(* Logix 5000 project; controller SV160E2_EDS_AOI_CompactLogix_RSLogix_V28 vendor 1 type 14 code 108 rev 28.11; software revision 28.00; part 2 of 4 *)

ADD_ON_INSTRUCTION AMCI_SV160E2_Home_CCW   (* revision 1.0, vendor AMCI, ExecuteEnableInFalse *)
// Revision note:
// 8/2019 Version 0 Initial release of SV160E2 Add On Instructions.
// 3/17/20 Version 1 replaced the generic EDS file with a more complete V1.6 EDS file.
VAR_INPUT
   Status_Word_0 : INT; {required}
        .11   // Set when there is an input error
        .12   // set when there is a command error
        .13   // set when there is a configuration error
        .0   // Set when the SV160E2 is moving CW
        .1   // Set when SV160E2 is moving CCW
        .7   // SV160E2 Move Complete bit
   Status_Word_1 : INT; {required}
        .15   // Set when SV160E2 is enabled
   Programmed_Speed : DINT; {required}
   Acceleration : INT; {required}
   Deceleration : INT; {required}
   Maximum_Move_Torque : INT;
END_VAR
VAR_IN_OUT
   AMCI_SV160E2_output_data : _000A:SV160E2_9125ACD4:O:0; {required}
END_VAR
VAR_OUTPUT
   EN : BOOL; {access Read Only, visible}   // AOI EN bit
   ER : BOOL; {access Read Only, visible}   // AOI ER bit
END_VAR
VAR
   command_data_block : INT[10];
        [1]   // Command Word 1
        [3]   // Lower Target Position
        [5]   // Lower Programmed Speed
        [0]   // Command Word 0
        [2]   // Upper Target Position
        [4]   // Upper Programmed Speed
END_VAR

ROUTINE EnableInFalse   (* ladder *)
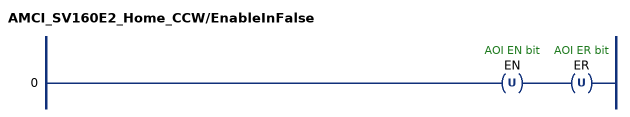
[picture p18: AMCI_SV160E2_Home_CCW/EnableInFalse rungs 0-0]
   0: OTU(EN)OTU(ER);
END_ROUTINE

ROUTINE Logic   (* ladder *)
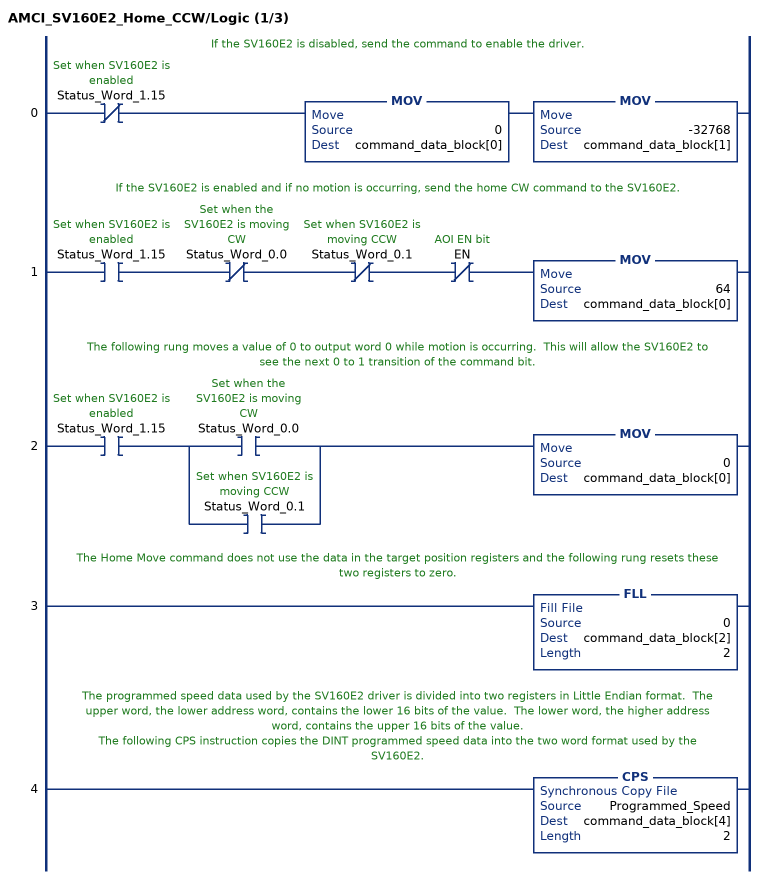
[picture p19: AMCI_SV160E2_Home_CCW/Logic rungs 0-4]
   // If the SV160E2 is disabled, send the command to enable the driver.
   0: XIO(Status_Word_1.15)MOV(0,command_data_block[0])MOV(-32768,command_data_block[1]);
   // If the SV160E2 is enabled and if no motion is occurring, send the home CW command to the SV160E2.
   1: XIC(Status_Word_1.15)XIO(Status_Word_0.0)XIO(Status_Word_0.1)XIO(EN)MOV(64,command_data_block[0]);
   // The following rung moves a value of 0 to output word 0 while motion is occurring.  This will allow the SV160E2 to see the next 0 to 1 transition of the command bit.
   2: XIC(Status_Word_1.15)[XIC(Status_Word_0.0) ,XIC(Status_Word_0.1) ]MOV(0,command_data_block[0]);
   // The Home Move command does not use the data in the target position registers and the following rung resets these two registers to zero.
   3: FLL(0,command_data_block[2],2);
   // The programmed speed data used by the SV160E2 driver is divided into two registers in Little Endian format.  The upper word, the lower address word, contains the lower 16 bits of the value.  The lower word, the higher address word, contains the upper 16 bits of the value.
   // The following CPS instruction copies the DINT programmed speed data into the two word format used by the SV160E2.
   4: CPS(Programmed_Speed,command_data_block[4],2);
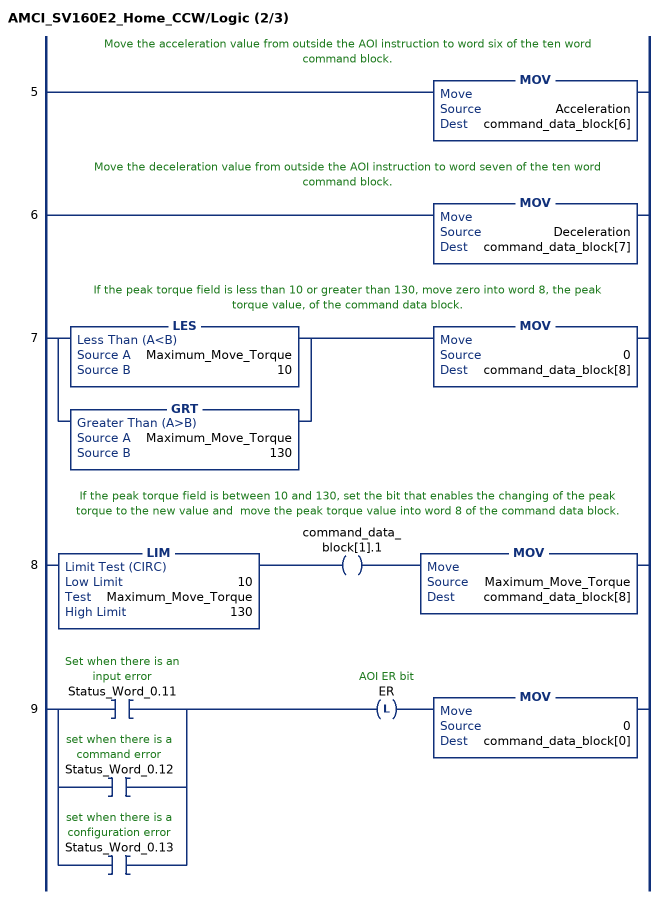
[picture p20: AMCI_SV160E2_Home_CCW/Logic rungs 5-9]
   // Move the acceleration value from outside the AOI instruction to word six of the ten word command block.
   5: MOV(Acceleration,command_data_block[6]);
   // Move the deceleration value from outside the AOI instruction to word seven of the ten word command block.
   6: MOV(Deceleration,command_data_block[7]);
   // If the peak torque field is less than 10 or greater than 130, move zero into word 8, the peak torque value, of the command data block.
   7: [LES(Maximum_Move_Torque,10) ,GRT(Maximum_Move_Torque,130) ]MOV(0,command_data_block[8]);
   // If the peak torque field is between 10 and 130, set the bit that enables the changing of the peak torque to the new value and  move the peak torque value into word 8 of the command data block.
   8: LIM(10,Maximum_Move_Torque,130)OTE(command_data_block[1].1)MOV(Maximum_Move_Torque,command_data_block[8]);
   9: [XIC(Status_Word_0.11) ,XIC(Status_Word_0.12) ,XIC(Status_Word_0.13) ]OTL(ER)MOV(0,command_data_block[0]);
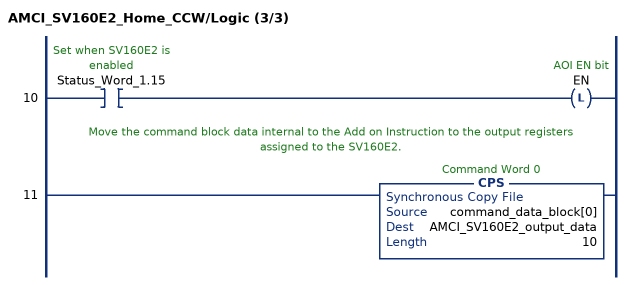
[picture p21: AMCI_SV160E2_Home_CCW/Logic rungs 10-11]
   10: XIC(Status_Word_1.15)OTL(EN);
   // Move the command block data internal to the Add on Instruction to the output registers assigned to the SV160E2.
   11: CPS(command_data_block[0],AMCI_SV160E2_output_data,10);
END_ROUTINE
END_ADD_ON_INSTRUCTION

ADD_ON_INSTRUCTION AMCI_SV160E2_Home_CW   (* revision 1.0, vendor AMCI, ExecuteEnableInFalse *)
// Revision note:
// 8/2019 Version 0 Initial release of SV160E2 Add On Instructions.
// 3/17/20 Version 1 replaced the generic EDS file with a more complete V1.6 EDS file.
VAR_INPUT
   Status_Word_0 : INT; {required}
        .11   // Set when there is an input error
        .12   // set when there is a command error
        .13   // set when there is a configuration error
        .0   // Set when the SV160E2 is moving CW
        .1   // Set when SV160E2 is moving CCW
        .7   // SV160E2 Move Complete bit
   Status_Word_1 : INT; {required}
        .15   // Set when SV160E2 is enabled
   Programmed_Speed : DINT; {required}
   Acceleration : INT; {required}
   Deceleration : INT; {required}
   Maximum_Move_Torque : INT;
END_VAR
VAR_IN_OUT
   AMCI_SV160E2_output_data : _000A:SV160E2_9125ACD4:O:0; {required}
END_VAR
VAR_OUTPUT
   EN : BOOL; {access Read Only, visible}   // AOI EN bit
   ER : BOOL; {access Read Only, visible}   // AOI ER bit
END_VAR
VAR
   command_data_block : INT[10];
        [1]   // Command Word 1
        [0]   // Command Word 0
        [3]   // Lower Target Position
        [5]   // Lower Programmed Speed
        [2]   // Upper Target Position
        [4]   // Upper Programmed Speed
END_VAR

ROUTINE EnableInFalse   (* ladder *)
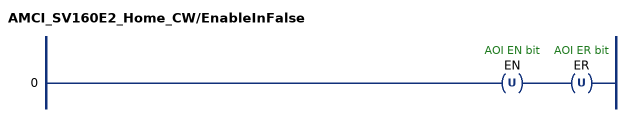
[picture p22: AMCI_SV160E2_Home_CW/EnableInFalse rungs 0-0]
   0: OTU(EN)OTU(ER);
END_ROUTINE

ROUTINE Logic   (* ladder *)
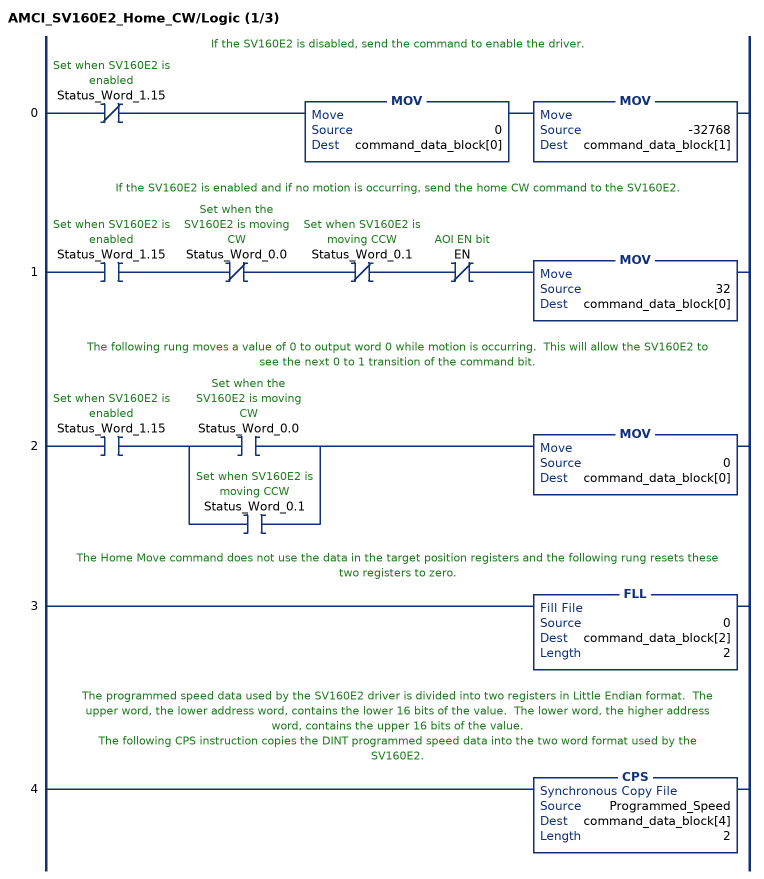
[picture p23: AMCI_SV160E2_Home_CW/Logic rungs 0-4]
   // If the SV160E2 is disabled, send the command to enable the driver.
   0: XIO(Status_Word_1.15)MOV(0,command_data_block[0])MOV(-32768,command_data_block[1]);
   // If the SV160E2 is enabled and if no motion is occurring, send the home CW command to the SV160E2.
   1: XIC(Status_Word_1.15)XIO(Status_Word_0.0)XIO(Status_Word_0.1)XIO(EN)MOV(32,command_data_block[0]);
   // The following rung moves a value of 0 to output word 0 while motion is occurring.  This will allow the SV160E2 to see the next 0 to 1 transition of the command bit.
   2: XIC(Status_Word_1.15)[XIC(Status_Word_0.0) ,XIC(Status_Word_0.1) ]MOV(0,command_data_block[0]);
   // The Home Move command does not use the data in the target position registers and the following rung resets these two registers to zero.
   3: FLL(0,command_data_block[2],2);
   // The programmed speed data used by the SV160E2 driver is divided into two registers in Little Endian format.  The upper word, the lower address word, contains the lower 16 bits of the value.  The lower word, the higher address word, contains the upper 16 bits of the value.
   // The following CPS instruction copies the DINT programmed speed data into the two word format used by the SV160E2.
   4: CPS(Programmed_Speed,command_data_block[4],2);
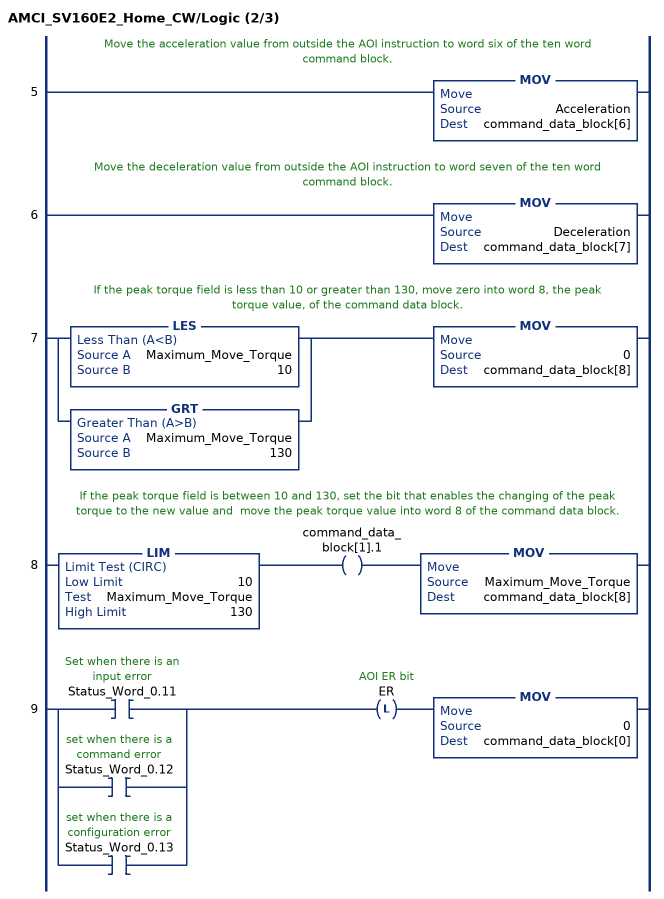
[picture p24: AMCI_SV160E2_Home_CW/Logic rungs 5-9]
   // Move the acceleration value from outside the AOI instruction to word six of the ten word command block.
   5: MOV(Acceleration,command_data_block[6]);
   // Move the deceleration value from outside the AOI instruction to word seven of the ten word command block.
   6: MOV(Deceleration,command_data_block[7]);
   // If the peak torque field is less than 10 or greater than 130, move zero into word 8, the peak torque value, of the command data block.
   7: [LES(Maximum_Move_Torque,10) ,GRT(Maximum_Move_Torque,130) ]MOV(0,command_data_block[8]);
   // If the peak torque field is between 10 and 130, set the bit that enables the changing of the peak torque to the new value and  move the peak torque value into word 8 of the command data block.
   8: LIM(10,Maximum_Move_Torque,130)OTE(command_data_block[1].1)MOV(Maximum_Move_Torque,command_data_block[8]);
   9: [XIC(Status_Word_0.11) ,XIC(Status_Word_0.12) ,XIC(Status_Word_0.13) ]OTL(ER)MOV(0,command_data_block[0]);
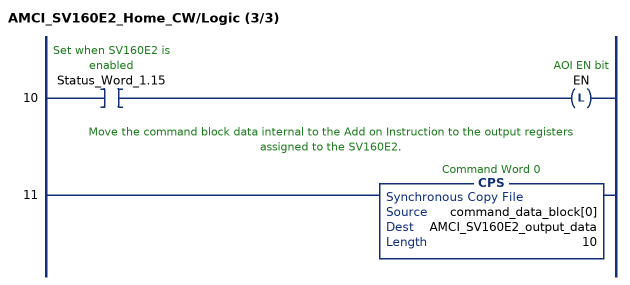
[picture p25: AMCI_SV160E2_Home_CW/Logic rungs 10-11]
   10: XIC(Status_Word_1.15)OTL(EN);
   // Move the command block data internal to the Add on Instruction to the output registers assigned to the SV160E2.
   11: CPS(command_data_block[0],AMCI_SV160E2_output_data,10);
END_ROUTINE
END_ADD_ON_INSTRUCTION

ADD_ON_INSTRUCTION AMCI_SV160E2_Immediate_Stop   (* revision 1.0, vendor AMCI *)
// Revision note:
// 8/2019 Version 0 Initial release of SV160E2 Add On Instructions.
// 3/17/20 Version 1 replaced the generic EDS file with a more complete V1.6 EDS file.
VAR_IN_OUT
   AMCI_SV160E2_OUTPUT_DATA : _000A:SV160E2_9125ACD4:O:0; {required}
END_VAR
VAR
   command_data_block : INT[10];
        [1]   // Command Bits LSW
        [0]   // Command Bits MSW
        [3]   // Lower Target Position
        [5]   // Lower Programmed Speed
        [2]   // Upper Target Position
        [4]   // Upper Programmed Speed
END_VAR

ROUTINE Logic   (* ladder *)
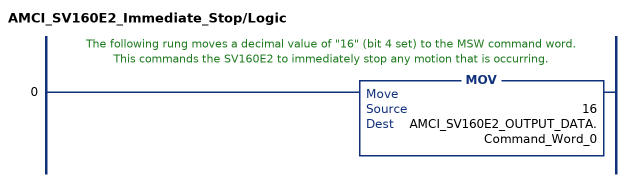
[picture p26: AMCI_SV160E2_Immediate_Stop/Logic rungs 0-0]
   // The following rung moves a decimal value of "16" (bit 4 set) to the MSW command word.  This commands the SV160E2 to immediately stop any motion that is occurring.
   0: MOV(16,AMCI_SV160E2_OUTPUT_DATA.Command_Word_0);
END_ROUTINE
END_ADD_ON_INSTRUCTION

ADD_ON_INSTRUCTION AMCI_SV160E2_Jog_CCW   (* revision 1.0, vendor AMCI, ExecuteEnableInFalse *)
// Revision note:
// 8/2019 Version 0 Initial release of SV160E2 Add On Instructions.
// 3/17/20 Version 1 replaced the generic EDS file with a more complete V1.6 EDS file.
VAR_INPUT
   Status_Word_0 : INT; {required}
        .11   // Set when there is an input error
        .12   // set when there is a command error
        .13   // set when there is a configuration error
        .0   // Set when the SV160E2 is moving CW
        .1   // Set when SV160E2 is moving CCW
        .3   // set when the SV160E2 is stopped
        .7   // SV160E2 Move Complete bit
   Status_Word_1 : INT; {required}
        .15   // Set when SV160E2 is enabled
   Programmed_Speed : DINT; {required}
   Acceleration : INT; {required}
   Deceleration : INT; {required}
   Maximum_Move_Torque : INT;
END_VAR
VAR_IN_OUT
   AMCI_SV160E2_output_data : _000A:SV160E2_9125ACD4:O:0; {required}
END_VAR
VAR_OUTPUT
   EN : BOOL; {access Read Only, visible}   // AOI EN bit
   jog_ccw_occurring : BOOL; {access Read Only, visible}
   ER : BOOL; {access Read Only, visible}   // AOI ER bit
END_VAR
VAR
   command_data_block : INT[10];
        [1]   // Command Word 1
        [3]   // Lower Target Position
        [5]   // Lower Programmed Speed
        [0]   // Command Word 0
        [2]   // Upper Target Position
        [4]   // Upper Programmed Speed
END_VAR

ROUTINE EnableInFalse   (* ladder *)
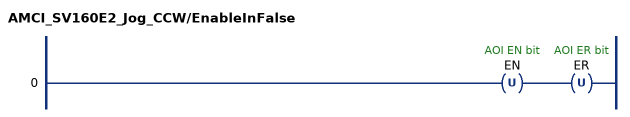
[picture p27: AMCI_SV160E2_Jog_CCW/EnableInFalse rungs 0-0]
   0: OTU(EN)OTU(ER);
END_ROUTINE

ROUTINE Logic   (* ladder *)
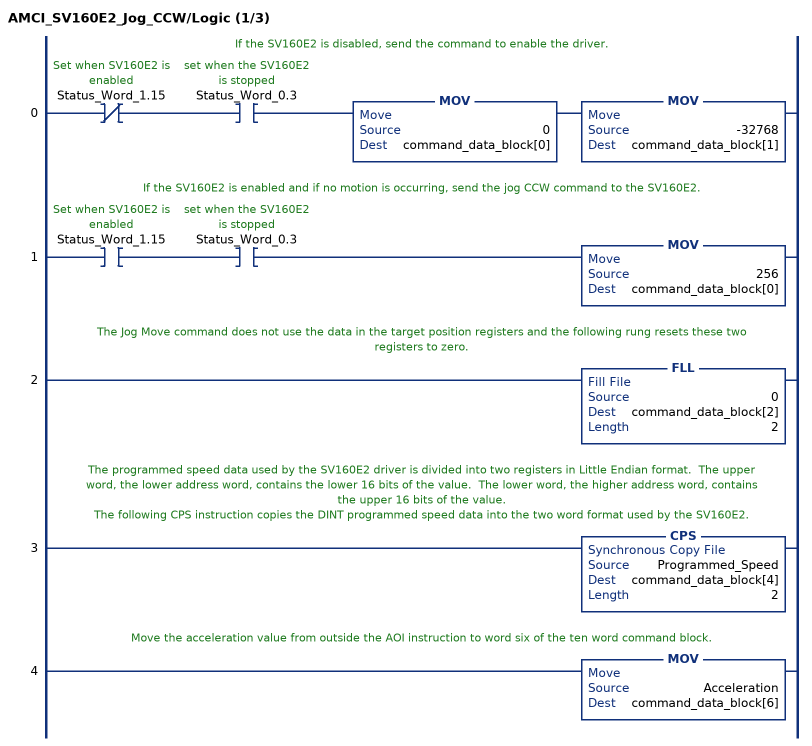
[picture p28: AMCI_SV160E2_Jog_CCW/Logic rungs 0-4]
   // If the SV160E2 is disabled, send the command to enable the driver.
   0: XIO(Status_Word_1.15)XIC(Status_Word_0.3)MOV(0,command_data_block[0])MOV(-32768,command_data_block[1]);
   // If the SV160E2 is enabled and if no motion is occurring, send the jog CCW command to the SV160E2.
   1: XIC(Status_Word_1.15)XIC(Status_Word_0.3)MOV(256,command_data_block[0]);
   // The Jog Move command does not use the data in the target position registers and the following rung resets these two registers to zero.
   2: FLL(0,command_data_block[2],2);
   // The programmed speed data used by the SV160E2 driver is divided into two registers in Little Endian format.  The upper word, the lower address word, contains the lower 16 bits of the value.  The lower word, the higher address word, contains the upper 16 bits of the value.
   // The following CPS instruction copies the DINT programmed speed data into the two word format used by the SV160E2.
   3: CPS(Programmed_Speed,command_data_block[4],2);
   // Move the acceleration value from outside the AOI instruction to word six of the ten word command block.
   4: MOV(Acceleration,command_data_block[6]);
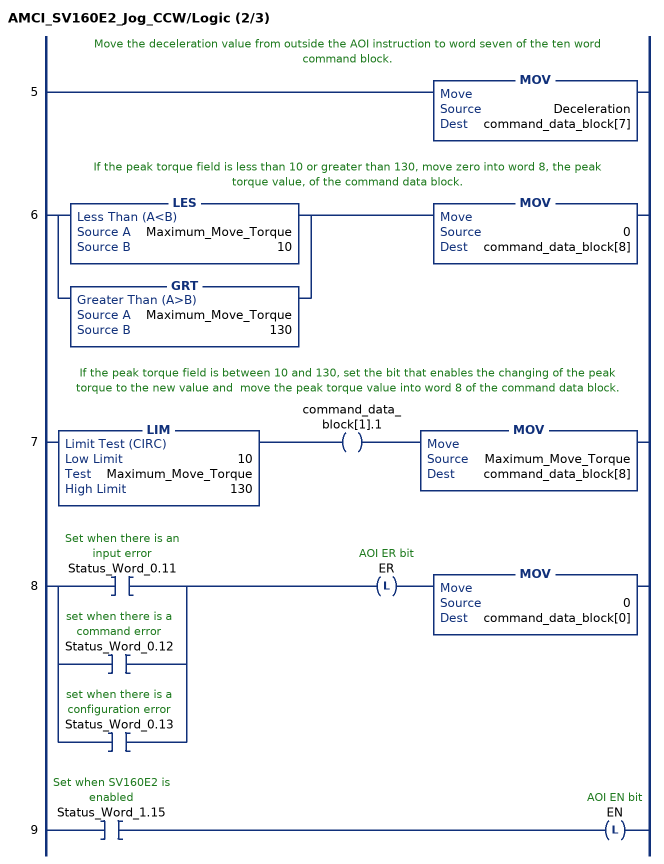
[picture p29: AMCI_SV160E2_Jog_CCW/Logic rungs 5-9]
   // Move the deceleration value from outside the AOI instruction to word seven of the ten word command block.
   5: MOV(Deceleration,command_data_block[7]);
   // If the peak torque field is less than 10 or greater than 130, move zero into word 8, the peak torque value, of the command data block.
   6: [LES(Maximum_Move_Torque,10) ,GRT(Maximum_Move_Torque,130) ]MOV(0,command_data_block[8]);
   // If the peak torque field is between 10 and 130, set the bit that enables the changing of the peak torque to the new value and  move the peak torque value into word 8 of the command data block.
   7: LIM(10,Maximum_Move_Torque,130)OTE(command_data_block[1].1)MOV(Maximum_Move_Torque,command_data_block[8]);
   8: [XIC(Status_Word_0.11) ,XIC(Status_Word_0.12) ,XIC(Status_Word_0.13) ]OTL(ER)MOV(0,command_data_block[0]);
   9: XIC(Status_Word_1.15)OTL(EN);
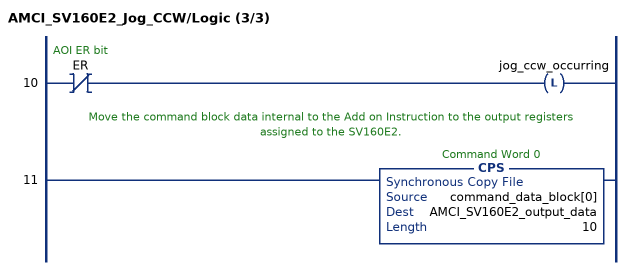
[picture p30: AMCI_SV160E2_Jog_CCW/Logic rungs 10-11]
   10: XIO(ER)OTL(jog_ccw_occurring);
   // Move the command block data internal to the Add on Instruction to the output registers assigned to the SV160E2.
   11: CPS(command_data_block[0],AMCI_SV160E2_output_data,10);
END_ROUTINE
END_ADD_ON_INSTRUCTION

ADD_ON_INSTRUCTION AMCI_SV160E2_Jog_CW   (* revision 1.0, vendor AMCI, ExecuteEnableInFalse *)
// Revision note:
// 8/2019 Version 0 Initial release of SV160E2 Add On Instructions.
// 3/17/20 Version 1 replaced the generic EDS file with a more complete V1.6 EDS file.
VAR_INPUT
   Status_Word_0 : INT; {required}
        .11   // Set when there is an input error
        .12   // set when there is a command error
        .13   // set when there is a configuration error
        .0   // Set when the SV160E2 is moving CW
        .1   // Set when SV160E2 is moving CCW
        .3   // set when the SV160E2 is stopped
        .7   // SV160E2 Move Complete bit
   Status_Word_1 : INT; {required}
        .15   // Set when SV160E2 is enabled
   Programmed_Speed : DINT; {required}
   Acceleration : INT; {required}
   Deceleration : INT; {required}
   Maximum_Move_Torque : INT;
END_VAR
VAR_IN_OUT
   AMCI_SV160E2_output_data : _000A:SV160E2_9125ACD4:O:0; {required}
END_VAR
VAR_OUTPUT
   EN : BOOL; {access Read Only, visible}   // AOI EN bit
   jog_cw_occurring : BOOL; {access Read Only, visible}
   ER : BOOL; {access Read Only, visible}   // AOI ER bit
END_VAR
VAR
   command_data_block : INT[10];
        [3]   // Lower Target Position
        [5]   // Lower Programmed Speed
        [2]   // Upper Target Position
        [4]   // Upper Programmed Speed
        [1]   // Command Word 1
        [0]   // Command Word 0
END_VAR

ROUTINE EnableInFalse   (* ladder *)
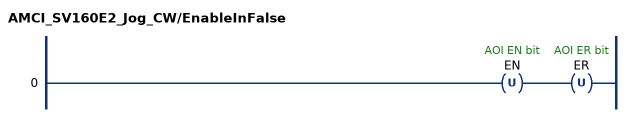
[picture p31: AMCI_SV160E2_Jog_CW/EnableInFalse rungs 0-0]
   0: OTU(EN)OTU(ER);
END_ROUTINE

ROUTINE Logic   (* ladder *)
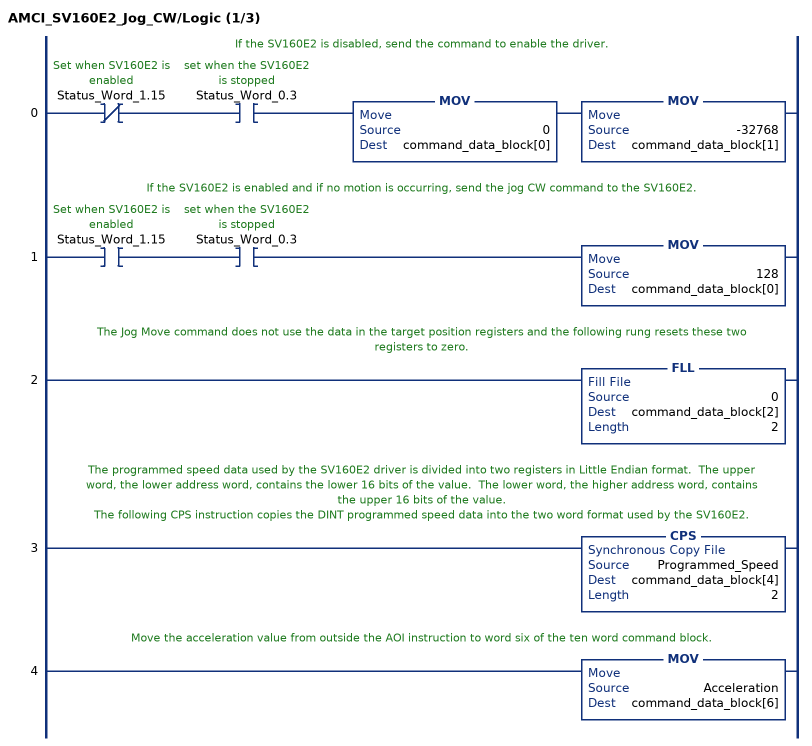
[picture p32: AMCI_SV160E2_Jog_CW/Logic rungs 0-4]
   // If the SV160E2 is disabled, send the command to enable the driver.
   0: XIO(Status_Word_1.15)XIC(Status_Word_0.3)MOV(0,command_data_block[0])MOV(-32768,command_data_block[1]);
   // If the SV160E2 is enabled and if no motion is occurring, send the jog CW command to the SV160E2.
   1: XIC(Status_Word_1.15)XIC(Status_Word_0.3)MOV(128,command_data_block[0]);
   // The Jog Move command does not use the data in the target position registers and the following rung resets these two registers to zero.
   2: FLL(0,command_data_block[2],2);
   // The programmed speed data used by the SV160E2 driver is divided into two registers in Little Endian format.  The upper word, the lower address word, contains the lower 16 bits of the value.  The lower word, the higher address word, contains the upper 16 bits of the value.
   // The following CPS instruction copies the DINT programmed speed data into the two word format used by the SV160E2.
   3: CPS(Programmed_Speed,command_data_block[4],2);
   // Move the acceleration value from outside the AOI instruction to word six of the ten word command block.
   4: MOV(Acceleration,command_data_block[6]);
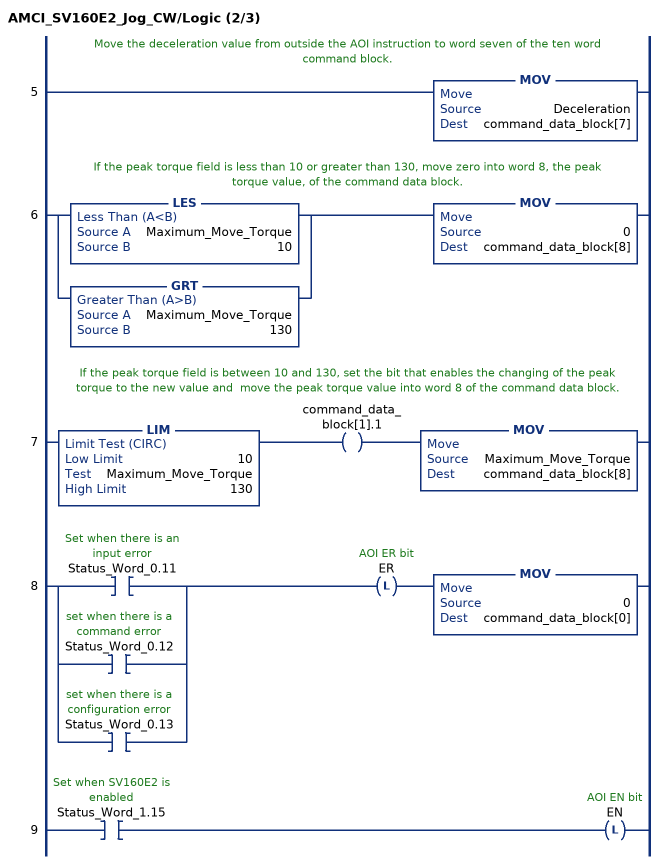
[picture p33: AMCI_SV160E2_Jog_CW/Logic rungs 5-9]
   // Move the deceleration value from outside the AOI instruction to word seven of the ten word command block.
   5: MOV(Deceleration,command_data_block[7]);
   // If the peak torque field is less than 10 or greater than 130, move zero into word 8, the peak torque value, of the command data block.
   6: [LES(Maximum_Move_Torque,10) ,GRT(Maximum_Move_Torque,130) ]MOV(0,command_data_block[8]);
   // If the peak torque field is between 10 and 130, set the bit that enables the changing of the peak torque to the new value and  move the peak torque value into word 8 of the command data block.
   7: LIM(10,Maximum_Move_Torque,130)OTE(command_data_block[1].1)MOV(Maximum_Move_Torque,command_data_block[8]);
   8: [XIC(Status_Word_0.11) ,XIC(Status_Word_0.12) ,XIC(Status_Word_0.13) ]OTL(ER)MOV(0,command_data_block[0]);
   9: XIC(Status_Word_1.15)OTL(EN);
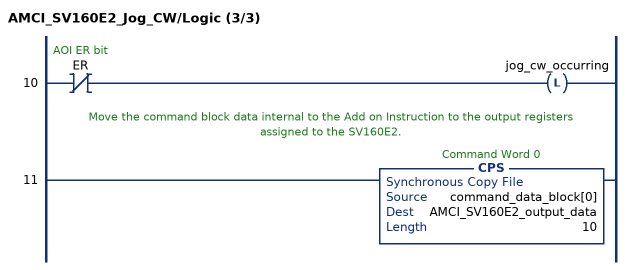
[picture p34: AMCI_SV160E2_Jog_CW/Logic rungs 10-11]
   10: XIO(ER)OTL(jog_cw_occurring);
   // Move the command block data internal to the Add on Instruction to the output registers assigned to the SV160E2.
   11: CPS(command_data_block[0],AMCI_SV160E2_output_data,10);
END_ROUTINE
END_ADD_ON_INSTRUCTION

ADD_ON_INSTRUCTION AMCI_SV160E2_Preset_on_Enable   (* revision 1.0, vendor AMCI, ExecuteEnableInFalse *)
// Revision note:
// 8/2019 Version 0 Initial release of SV160E2 Add On Instructions.
// 3/17/20 Version 1 replaced the generic EDS file with a more complete V1.6 EDS file.
VAR_IN_OUT
   AMCI_SV160E2_output_data : _000A:SV160E2_9125ACD4:O:0; {required}
END_VAR
VAR_OUTPUT
   EN : BOOL; {access Read Only, visible}
END_VAR
VAR
   command_data_block : INT[10];
        [1]   // Command Word 1
        [0]   // Command Word 0
        [3]   // Lower Target Position
        [5]   // Lower Programmed Speed
END_VAR

ROUTINE EnableInFalse   (* ladder *)
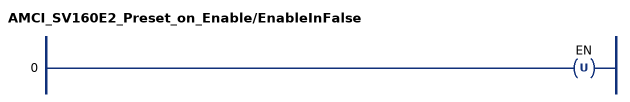
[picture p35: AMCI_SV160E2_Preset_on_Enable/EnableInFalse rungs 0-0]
   0: OTU(EN);
END_ROUTINE
(* Logix 5000 project; controller SV160E2_EDS_AOI_CompactLogix_RSLogix_V28 vendor 1 type 14 code 108 rev 28.11; software revision 28.00; part 3 of 4 *)
(* AMCI_SV160E2_Preset_on_Enable, continued *)

ROUTINE Logic   (* ladder *)
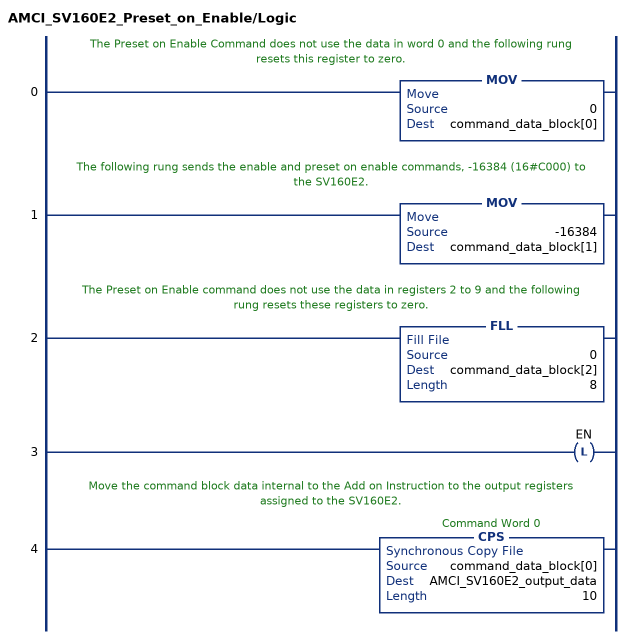
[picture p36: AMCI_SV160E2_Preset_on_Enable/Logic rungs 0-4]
   // The Preset on Enable Command does not use the data in word 0 and the following rung resets this register to zero.
   0: MOV(0,command_data_block[0]);
   // The following rung sends the enable and preset on enable commands, -16384 (16#C000) to the SV160E2.
   1: MOV(-16384,command_data_block[1]);
   // The Preset on Enable command does not use the data in registers 2 to 9 and the following rung resets these registers to zero.
   2: FLL(0,command_data_block[2],8);
   3: OTL(EN);
   // Move the command block data internal to the Add on Instruction to the output registers assigned to the SV160E2.
   4: CPS(command_data_block[0],AMCI_SV160E2_output_data,10);
END_ROUTINE
END_ADD_ON_INSTRUCTION

ADD_ON_INSTRUCTION AMCI_SV160E2_Preset_Position   (* revision 1.0, vendor AMCI, ExecuteEnableInFalse *)
// Revision note:
// 8/2019 Version 0 Initial release of SV160E2 Add On Instructions.
// 3/17/20 Version 1 replaced the generic EDS file with a more complete V1.6 EDS file.
VAR_INPUT
   Status_Word_0 : INT; {required}
        .11   // Set when there is an input error
        .12   // set when there is a command error
        .13   // set when there is a configuration error
        .0   // Set when the SV160E2 is moving CW
        .1   // Set when SV160E2 is moving CCW
        .7   // SV160E2 Move Complete bit
   Status_Word_1 : INT; {required}
        .15   // Set when SV160E2 is enabled
   save_in_flash_0_no_1_yes : BOOL; {required}
   Target_Position : DINT; {required}
END_VAR
VAR_IN_OUT
   AMCI_SV160E2_output_data : _000A:SV160E2_9125ACD4:O:0; {required}
END_VAR
VAR_OUTPUT
   EN : BOOL; {visible}
END_VAR
VAR
   command_data_block : INT[10];
        [5]   // Lower Programmed Speed
        [2]   // Upper Target Position
        [1]   // Command Word 1
        [0]   // Command Word 0
        [3]   // Lower Target Position
END_VAR

ROUTINE EnableInFalse   (* ladder *)
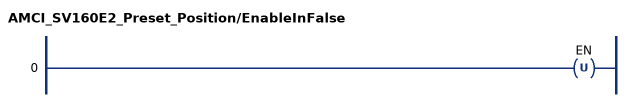
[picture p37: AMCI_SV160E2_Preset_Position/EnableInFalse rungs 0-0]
   0: OTU(EN);
END_ROUTINE

ROUTINE Logic   (* ladder *)
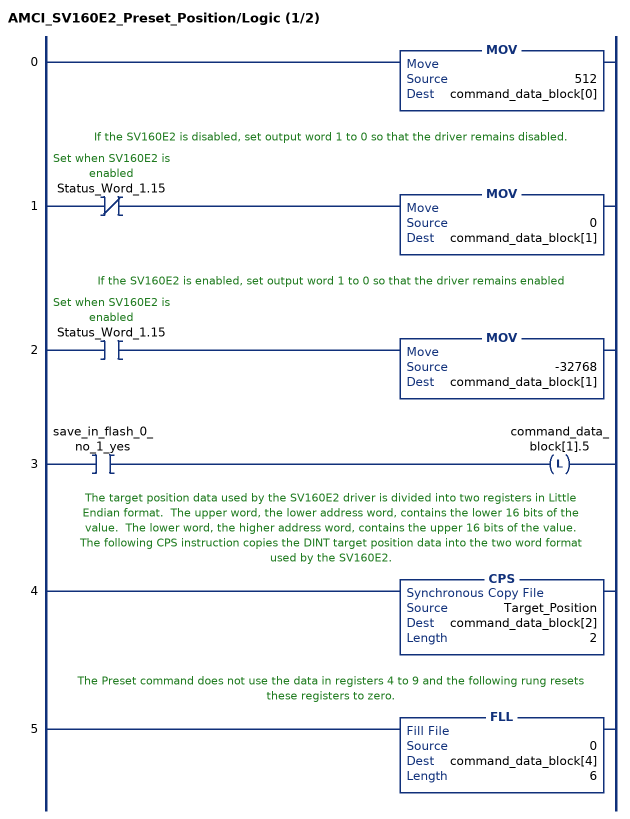
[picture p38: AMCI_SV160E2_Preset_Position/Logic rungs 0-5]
   0: MOV(512,command_data_block[0]);
   // If the SV160E2 is disabled, set output word 1 to 0 so that the driver remains disabled.
   1: XIO(Status_Word_1.15)MOV(0,command_data_block[1]);
   // If the SV160E2 is enabled, set output word 1 to 0 so that the driver remains enabled
   2: XIC(Status_Word_1.15)MOV(-32768,command_data_block[1]);
   3: XIC(save_in_flash_0_no_1_yes)OTL(command_data_block[1].5);
   // The target position data used by the SV160E2 driver is divided into two registers in Little Endian format.  The upper word, the lower address word, contains the lower 16 bits of the value.  The lower word, the higher address word, contains the upper 16 bits of the value.
   // The following CPS instruction copies the DINT target position data into the two word format used by the SV160E2.
   4: CPS(Target_Position,command_data_block[2],2);
   // The Preset command does not use the data in registers 4 to 9 and the following rung resets these registers to zero.
   5: FLL(0,command_data_block[4],6);
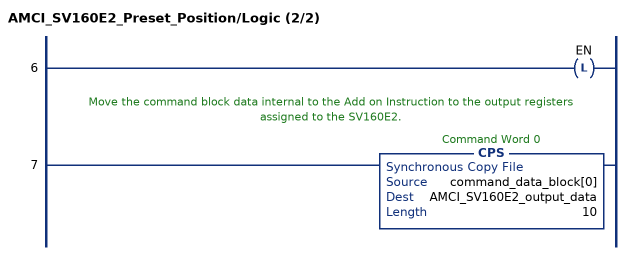
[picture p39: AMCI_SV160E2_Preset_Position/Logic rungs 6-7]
   6: OTL(EN);
   // Move the command block data internal to the Add on Instruction to the output registers assigned to the SV160E2.
   7: CPS(command_data_block[0],AMCI_SV160E2_output_data,10);
END_ROUTINE
END_ADD_ON_INSTRUCTION

ADD_ON_INSTRUCTION AMCI_SV160E2_Registration_Move_CCW   (* revision 1.0, vendor AMCI, ExecuteEnableInFalse *)
// Revision note:
// 8/2019 Version 0 Initial release of SV160E2 Add On Instructions.
// 3/17/20 Version 1 replaced the generic EDS file with a more complete V1.6 EDS file.
VAR_INPUT
   Status_Word_0 : INT; {required}
   Status_Word_1 : INT; {required}
   Type_0_for_standard_1_for_indexed : BOOL;
   Stopping_Distance : DINT; {required}
   Programmed_Speed : DINT; {required}
   Acceleration : INT; {required}
   Deceleration : INT; {required}
   Minimum_Registration_Move_Distance : DINT; {required}
END_VAR
VAR_IN_OUT
   AMCI_SV160E2_output_data : _000A:SV160E2_9125ACD4:O:0; {required}
END_VAR
VAR_OUTPUT
   EN : BOOL; {visible}
   Registration_Move_CW_Occurring : BOOL; {access Read Only, visible}
   ER : BOOL; {visible}
END_VAR
VAR
   Upper_Result_X_1000 : DINT;
   command_data_block : INT[10];
        [1]   // Command Bits LSW
        [0]   // Command Bits MSW
        [3]   // Lower Target Position
        [5]   // Lower Programmed Speed
        [2]   // Upper Target Position
        [4]   // Upper Programmed Speed
END_VAR

ROUTINE EnableInFalse   (* ladder *)
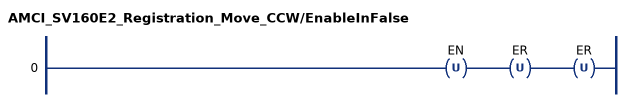
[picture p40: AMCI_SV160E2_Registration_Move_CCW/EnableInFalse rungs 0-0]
   0: OTU(EN)OTU(ER)OTU(ER);
END_ROUTINE

ROUTINE Logic   (* ladder *)
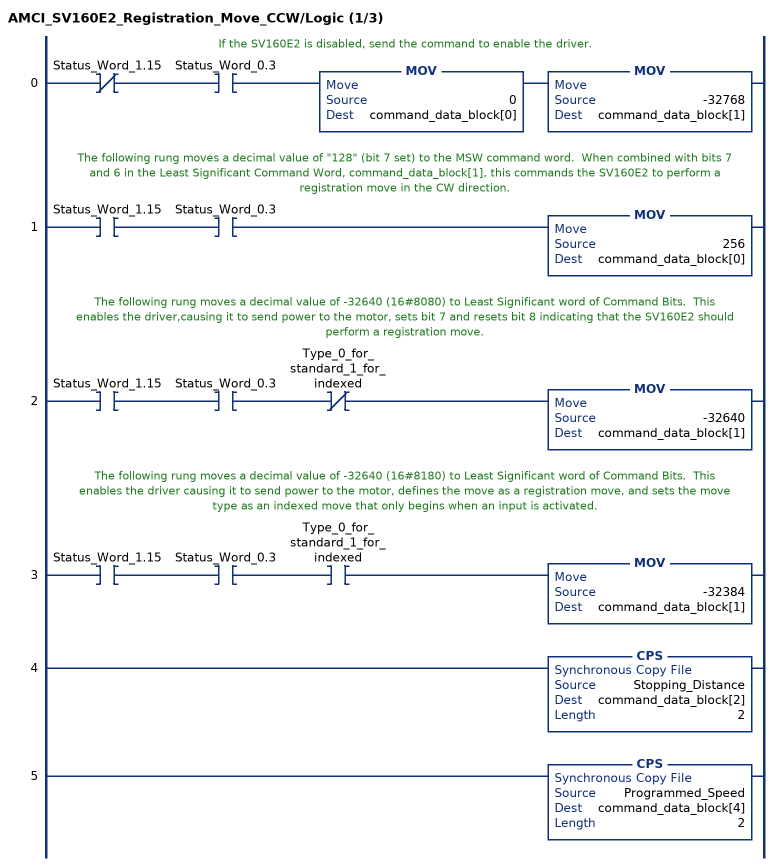
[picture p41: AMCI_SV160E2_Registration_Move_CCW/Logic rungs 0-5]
   // If the SV160E2 is disabled, send the command to enable the driver.
   0: XIO(Status_Word_1.15)XIC(Status_Word_0.3)MOV(0,command_data_block[0])MOV(-32768,command_data_block[1]);
   // The following rung moves a decimal value of "128" (bit 7 set) to the MSW command word.  When combined with bits 7 and 6 in the Least Significant Command Word, command_data_block[1], this commands the SV160E2 to perform a registration move in the CW direction.
   1: XIC(Status_Word_1.15)XIC(Status_Word_0.3)MOV(256,command_data_block[0]);
   // The following rung moves a decimal value of -32640 (16#8080) to Least Significant word of Command Bits.  This enables the driver,causing it to send power to the motor, sets bit 7 and resets bit 8 indicating that the SV160E2 should perform a registration move.
   2: XIC(Status_Word_1.15)XIC(Status_Word_0.3)XIO(Type_0_for_standard_1_for_indexed)MOV(-32640,command_data_block[1]);
   // The following rung moves a decimal value of -32640 (16#8180) to Least Significant word of Command Bits.  This enables the driver causing it to send power to the motor, defines the move as a registration move, and sets the move type as an indexed move that only begins when an input is activated.
   3: XIC(Status_Word_1.15)XIC(Status_Word_0.3)XIC(Type_0_for_standard_1_for_indexed)MOV(-32384,command_data_block[1]);
   4: CPS(Stopping_Distance,command_data_block[2],2);
   5: CPS(Programmed_Speed,command_data_block[4],2);
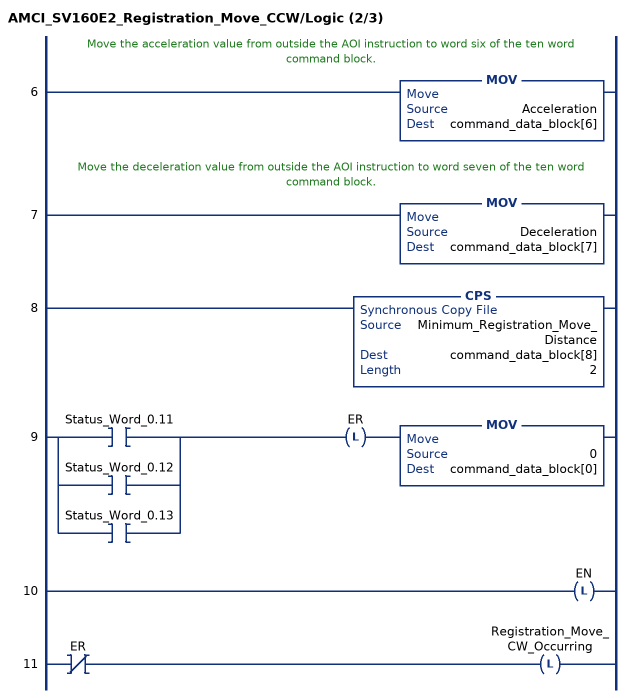
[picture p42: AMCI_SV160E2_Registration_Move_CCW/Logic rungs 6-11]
   // Move the acceleration value from outside the AOI instruction to word six of the ten word command block.
   6: MOV(Acceleration,command_data_block[6]);
   // Move the deceleration value from outside the AOI instruction to word seven of the ten word command block.
   7: MOV(Deceleration,command_data_block[7]);
   8: CPS(Minimum_Registration_Move_Distance,command_data_block[8],2);
   9: [XIC(Status_Word_0.11) ,XIC(Status_Word_0.12) ,XIC(Status_Word_0.13) ]OTL(ER)MOV(0,command_data_block[0]);
   10: OTL(EN);
   11: XIO(ER)OTL(Registration_Move_CW_Occurring);
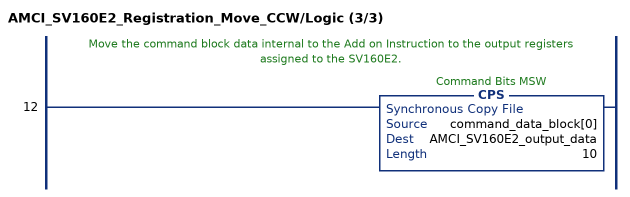
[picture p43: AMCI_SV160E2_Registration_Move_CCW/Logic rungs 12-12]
   // Move the command block data internal to the Add on Instruction to the output registers assigned to the SV160E2.
   12: CPS(command_data_block[0],AMCI_SV160E2_output_data,10);
END_ROUTINE
END_ADD_ON_INSTRUCTION

ADD_ON_INSTRUCTION AMCI_SV160E2_Registration_Move_CW   (* revision 1.0, vendor AMCI, ExecuteEnableInFalse *)
// Revision note:
// 8/2019 Version 0 Initial release of SV160E2 Add On Instructions.
// 3/17/20 Version 1 replaced the generic EDS file with a more complete V1.6 EDS file.
VAR_INPUT
   Status_Word_0 : INT; {required}
   Status_Word_1 : INT; {required}
   Type_0_for_standard_1_for_indexed : BOOL;
   Stopping_Distance : DINT; {required}
   Programmed_Speed : DINT; {required}
   Acceleration : INT; {required}
   Deceleration : INT; {required}
   Minimum_Registration_Move_Distance : DINT; {required}
END_VAR
VAR_IN_OUT
   AMCI_SV160E2_output_data : _000A:SV160E2_9125ACD4:O:0; {required}
END_VAR
VAR_OUTPUT
   EN : BOOL; {visible}
   Registration_Move_CW_Occurring : BOOL; {access Read Only, visible}
   ER : BOOL; {visible}
END_VAR
VAR
   Upper_Result_X_1000 : DINT;
   command_data_block : INT[10];
        [2]   // Upper Target Position
        [1]   // Command Bits LSW
        [5]   // Lower Programmed Speed
        [4]   // Upper Programmed Speed
        [0]   // Command Bits MSW
        [3]   // Lower Target Position
END_VAR

ROUTINE EnableInFalse   (* ladder *)
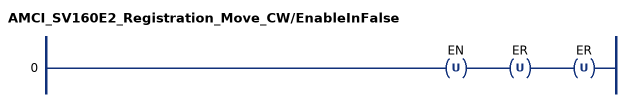
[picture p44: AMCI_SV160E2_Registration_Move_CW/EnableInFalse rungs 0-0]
   0: OTU(EN)OTU(ER)OTU(ER);
END_ROUTINE

ROUTINE Logic   (* ladder *)
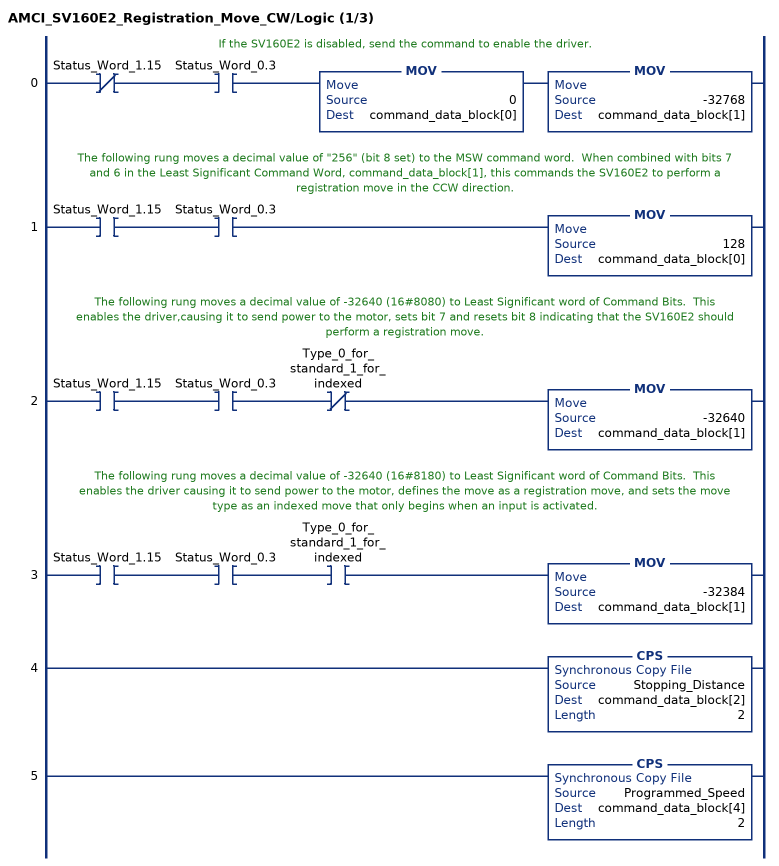
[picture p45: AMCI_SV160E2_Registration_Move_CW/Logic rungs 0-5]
   // If the SV160E2 is disabled, send the command to enable the driver.
   0: XIO(Status_Word_1.15)XIC(Status_Word_0.3)MOV(0,command_data_block[0])MOV(-32768,command_data_block[1]);
   // The following rung moves a decimal value of "256" (bit 8 set) to the MSW command word.  When combined with bits 7 and 6 in the Least Significant Command Word, command_data_block[1], this commands the SV160E2 to perform a registration move in the CCW direction.
   1: XIC(Status_Word_1.15)XIC(Status_Word_0.3)MOV(128,command_data_block[0]);
   // The following rung moves a decimal value of -32640 (16#8080) to Least Significant word of Command Bits.  This enables the driver,causing it to send power to the motor, sets bit 7 and resets bit 8 indicating that the SV160E2 should perform a registration move.
   2: XIC(Status_Word_1.15)XIC(Status_Word_0.3)XIO(Type_0_for_standard_1_for_indexed)MOV(-32640,command_data_block[1]);
   // The following rung moves a decimal value of -32640 (16#8180) to Least Significant word of Command Bits.  This enables the driver causing it to send power to the motor, defines the move as a registration move, and sets the move type as an indexed move that only begins when an input is activated.
   3: XIC(Status_Word_1.15)XIC(Status_Word_0.3)XIC(Type_0_for_standard_1_for_indexed)MOV(-32384,command_data_block[1]);
   4: CPS(Stopping_Distance,command_data_block[2],2);
   5: CPS(Programmed_Speed,command_data_block[4],2);
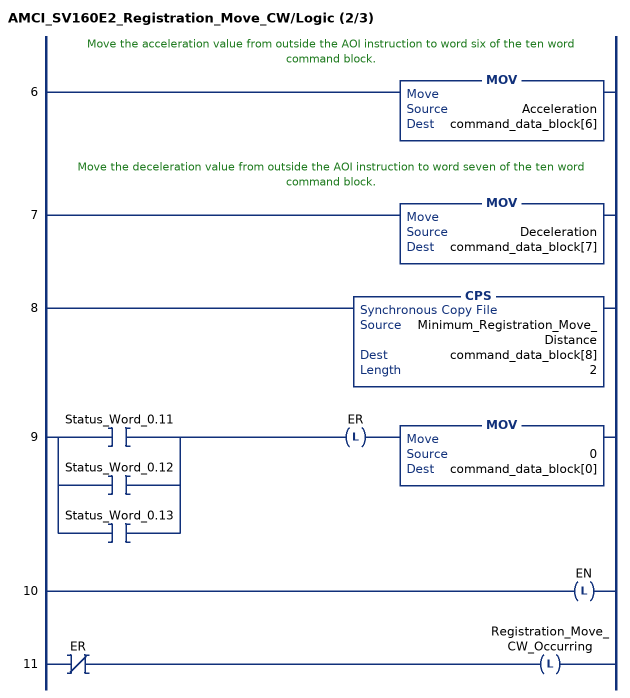
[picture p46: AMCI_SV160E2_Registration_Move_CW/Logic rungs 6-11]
   // Move the acceleration value from outside the AOI instruction to word six of the ten word command block.
   6: MOV(Acceleration,command_data_block[6]);
   // Move the deceleration value from outside the AOI instruction to word seven of the ten word command block.
   7: MOV(Deceleration,command_data_block[7]);
   8: CPS(Minimum_Registration_Move_Distance,command_data_block[8],2);
   9: [XIC(Status_Word_0.11) ,XIC(Status_Word_0.12) ,XIC(Status_Word_0.13) ]OTL(ER)MOV(0,command_data_block[0]);
   10: OTL(EN);
   11: XIO(ER)OTL(Registration_Move_CW_Occurring);
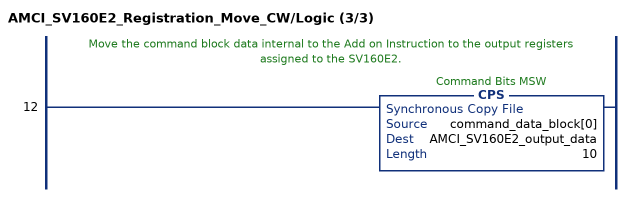
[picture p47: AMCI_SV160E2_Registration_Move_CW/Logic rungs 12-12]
   // Move the command block data internal to the Add on Instruction to the output registers assigned to the SV160E2.
   12: CPS(command_data_block[0],AMCI_SV160E2_output_data,10);
END_ROUTINE
END_ADD_ON_INSTRUCTION

ADD_ON_INSTRUCTION AMCI_SV160E2_Relative_Move   (* revision 1.0, vendor AMCI, ExecuteEnableInFalse *)
// Revision note:
// 8/2019 Version 0 Initial release of SV160E2 Add On Instructions.
// 3/17/20 Version 1 replaced the generic EDS file with a more complete V1.6 EDS file.
VAR_INPUT
   Status_Word_0 : INT; {required}
        .11   // Set when there is an input error
        .12   // set when there is a command error
        .13   // set when there is a configuration error
        .0   // Set when the SV160E2 is moving CW
        .1   // Set when SV160E2 is moving CCW
        .7   // SV160E2 Move Complete bit
   Status_Word_1 : INT; {required}
        .15   // Set when SV160E2 is enabled
   Type_0_for_standard_1_for_indexed : BOOL;
   Target_Position : DINT; {required}
   Programmed_Speed : DINT; {required}
   Acceleration : INT; {required}
   Deceleration : INT; {required}
   Maximum_Move_Torque : INT;
END_VAR
VAR_IN_OUT
   AMCI_SV160E2_output_data : _000A:SV160E2_9125ACD4:O:0; {required}
END_VAR
VAR_OUTPUT
   EN : BOOL; {access Read Only, visible}   // AOI EN bit
   ER : BOOL; {access Read Only, visible}   // AOI ER bit
END_VAR
VAR
   command_data_block : INT[10];
        [2]   // Upper Target Position
        [4]   // Upper Programmed Speed
        [1]   // Command Word 1
        [3]   // Lower Target Position
        [5]   // Lower Programmed Speed
        [0]   // Command Word 0
END_VAR

ROUTINE EnableInFalse   (* ladder *)
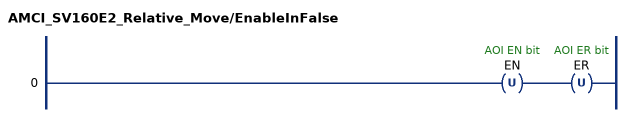
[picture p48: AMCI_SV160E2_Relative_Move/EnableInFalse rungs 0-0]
   0: OTU(EN)OTU(ER);
END_ROUTINE

ROUTINE Logic   (* ladder *)
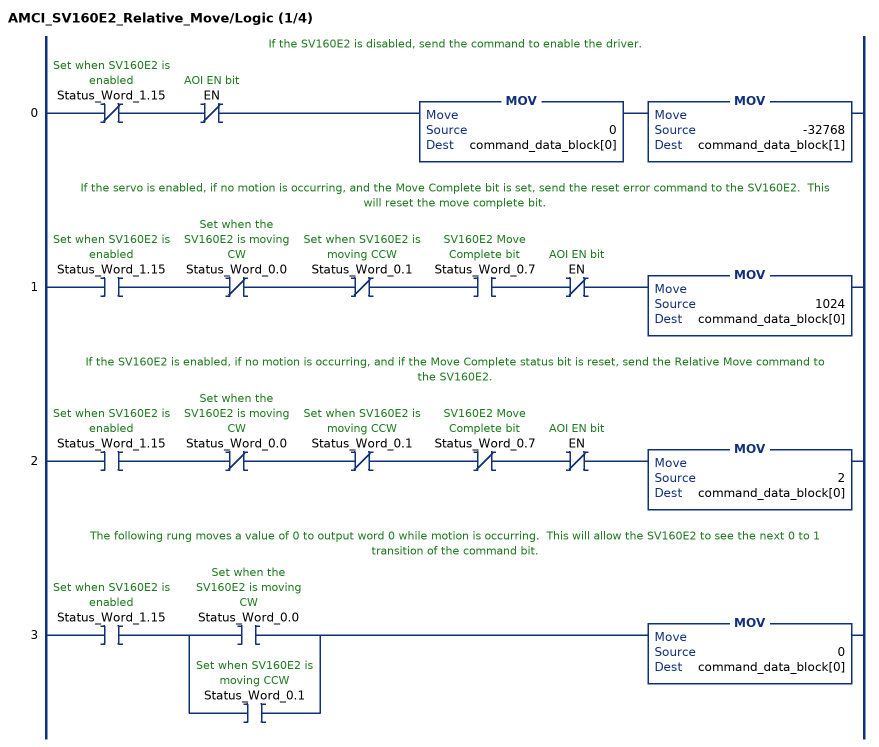
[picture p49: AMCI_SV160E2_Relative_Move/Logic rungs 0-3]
   // If the SV160E2 is disabled, send the command to enable the driver.
   0: XIO(Status_Word_1.15)XIO(EN)MOV(0,command_data_block[0])MOV(-32768,command_data_block[1]);
   // If the servo is enabled, if no motion is occurring, and the Move Complete bit is set, send the reset error command to the SV160E2.  This will reset the move complete bit.
   1: XIC(Status_Word_1.15)XIO(Status_Word_0.0)XIO(Status_Word_0.1)XIC(Status_Word_0.7)XIO(EN)MOV(1024,command_data_block[0]);
   // If the SV160E2 is enabled, if no motion is occurring, and if the Move Complete status bit is reset, send the Relative Move command to the SV160E2.
   2: XIC(Status_Word_1.15)XIO(Status_Word_0.0)XIO(Status_Word_0.1)XIO(Status_Word_0.7)XIO(EN)MOV(2,command_data_block[0]);
   // The following rung moves a value of 0 to output word 0 while motion is occurring.  This will allow the SV160E2 to see the next 0 to 1 transition of the command bit.
   3: XIC(Status_Word_1.15)[XIC(Status_Word_0.0) ,XIC(Status_Word_0.1) ]MOV(0,command_data_block[0]);
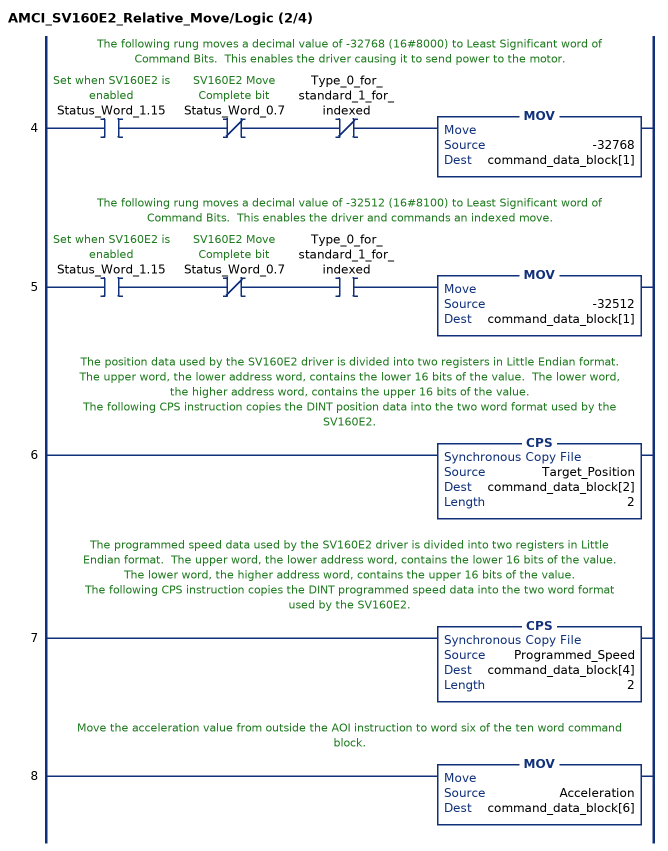
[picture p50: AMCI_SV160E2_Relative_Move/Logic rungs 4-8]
   // The following rung moves a decimal value of -32768 (16#8000) to Least Significant word of Command Bits.  This enables the driver causing it to send power to the motor.
   4: XIC(Status_Word_1.15)XIO(Status_Word_0.7)XIO(Type_0_for_standard_1_for_indexed)MOV(-32768,command_data_block[1]);
   // The following rung moves a decimal value of -32512 (16#8100) to Least Significant word of Command Bits.  This enables the driver and commands an indexed move.
   5: XIC(Status_Word_1.15)XIO(Status_Word_0.7)XIC(Type_0_for_standard_1_for_indexed)MOV(-32512,command_data_block[1]);
   // The position data used by the SV160E2 driver is divided into two registers in Little Endian format.  The upper word, the lower address word, contains the lower 16 bits of the value.  The lower word, the higher address word, contains the upper 16 bits of the value.
   // The following CPS instruction copies the DINT position data into the two word format used by the SV160E2.
   6: CPS(Target_Position,command_data_block[2],2);
   // The programmed speed data used by the SV160E2 driver is divided into two registers in Little Endian format.  The upper word, the lower address word, contains the lower 16 bits of the value.  The lower word, the higher address word, contains the upper 16 bits of the value.
   // The following CPS instruction copies the DINT programmed speed data into the two word format used by the SV160E2.
   7: CPS(Programmed_Speed,command_data_block[4],2);
   // Move the acceleration value from outside the AOI instruction to word six of the ten word command block.
   8: MOV(Acceleration,command_data_block[6]);
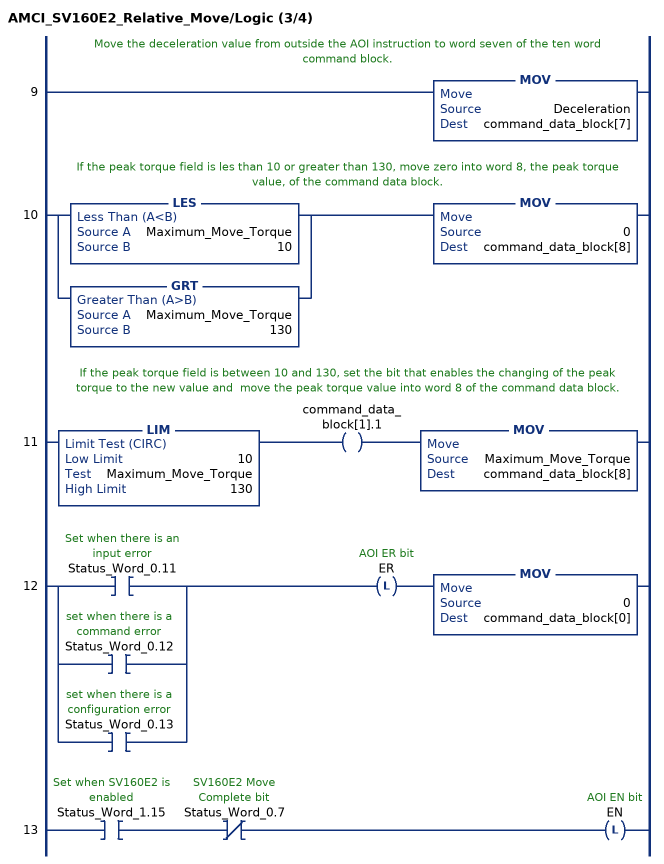
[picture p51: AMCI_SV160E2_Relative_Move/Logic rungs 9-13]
   // Move the deceleration value from outside the AOI instruction to word seven of the ten word command block.
   9: MOV(Deceleration,command_data_block[7]);
   // If the peak torque field is les than 10 or greater than 130, move zero into word 8, the peak torque value, of the command data block.
   10: [LES(Maximum_Move_Torque,10) ,GRT(Maximum_Move_Torque,130) ]MOV(0,command_data_block[8]);
   // If the peak torque field is between 10 and 130, set the bit that enables the changing of the peak torque to the new value and  move the peak torque value into word 8 of the command data block.
   11: LIM(10,Maximum_Move_Torque,130)OTE(command_data_block[1].1)MOV(Maximum_Move_Torque,command_data_block[8]);
   12: [XIC(Status_Word_0.11) ,XIC(Status_Word_0.12) ,XIC(Status_Word_0.13) ]OTL(ER)MOV(0,command_data_block[0]);
   13: XIC(Status_Word_1.15)XIO(Status_Word_0.7)OTL(EN);
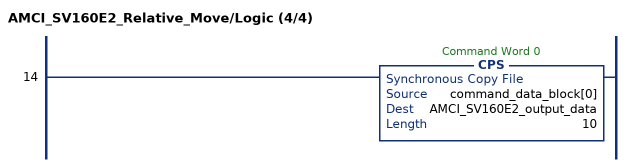
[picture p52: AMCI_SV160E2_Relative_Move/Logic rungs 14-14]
   14: CPS(command_data_block[0],AMCI_SV160E2_output_data,10);
END_ROUTINE
END_ADD_ON_INSTRUCTION

ADD_ON_INSTRUCTION AMCI_SV160E2_Reset_Errors   (* revision 1.0, vendor AMCI *)
// Revision note:
// 8/2019 Version 0 Initial release of SV160E2 Add On Instructions.
// 3/17/20 Version 1 replaced the generic EDS file with a more complete V1.6 EDS file.
VAR_IN_OUT
   AMCI_SV160E2_OUTPUT_DATA : _000A:SV160E2_9125ACD4:O:0; {required}
END_VAR
VAR
   command_data_block : INT[10];
        [1]   // Command Bits LSW
        [3]   // Lower Target Position
        [2]   // Upper Target Position
        [0]   // Command Bits MSW
        [5]   // Lower Programmed Speed
        [4]   // Upper Programmed Speed
END_VAR

ROUTINE Logic   (* ladder *)
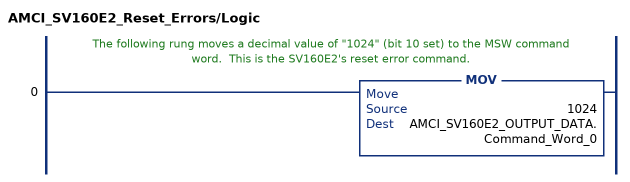
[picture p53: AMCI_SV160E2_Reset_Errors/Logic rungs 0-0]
   // The following rung moves a decimal value of "1024" (bit 10 set) to the MSW command word.  This is the SV160E2's reset error command.
   0: MOV(1024,AMCI_SV160E2_OUTPUT_DATA.Command_Word_0);
END_ROUTINE
END_ADD_ON_INSTRUCTION
(* Logix 5000 project; controller SV160E2_EDS_AOI_CompactLogix_RSLogix_V28 vendor 1 type 14 code 108 rev 28.11; software revision 28.00; part 4 of 4 *)

ADD_ON_INSTRUCTION AMCI_SV160E2_Resume   (* revision 1.0, vendor AMCI *)
// Revision note:
// 8/2019 Version 0 Initial release of SV160E2 Add On Instructions.
// 3/17/20 Version 1 replaced the generic EDS file with a more complete V1.6 EDS file.
VAR_IN_OUT
   amci_sv160e2_output_data : _000A:SV160E2_9125ACD4:O:0; {required}
END_VAR
VAR
   command_data_block : INT[10];
        [1]   // Command Bits LSW
        [3]   // Lower Target Position
        [5]   // Lower Programmed Speed
        [0]   // Command Bits MSW
        [2]   // Upper Target Position
        [4]   // Upper Programmed Speed
END_VAR

ROUTINE Logic   (* ladder *)
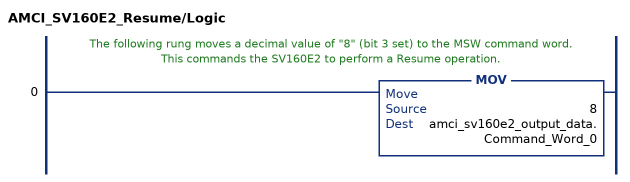
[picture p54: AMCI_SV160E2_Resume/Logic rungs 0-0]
   // The following rung moves a decimal value of "8" (bit 3 set) to the MSW command word.  This commands the SV160E2 to perform a Resume operation.
   0: MOV(8,amci_sv160e2_output_data.Command_Word_0);
END_ROUTINE
END_ADD_ON_INSTRUCTION

ADD_ON_INSTRUCTION AMCI_SV160E2_Tuning   (* revision 1.0, vendor AMCI, ExecuteEnableInFalse *)
// Revision note:
// 8/2019 Version 0 Initial release of SV160E2 Add On Instructions.
// 3/17/20 Version 1 replaced the generic EDS file with a more complete V1.6 EDS file.
VAR_INPUT
   Status_Word_0 : INT; {required}
        .11   // Set when there is an input error
        .12   // set when there is a command error
        .13   // set when there is a configuration error
        .0   // Set when the SV160E2 is moving CW
        .1   // Set when SV160E2 is moving CCW
        .7   // SV160E2 Move Complete bit
   Status_Word_1 : INT; {required}
        .15   // Set when SV160E2 is enabled
   Veloctiy_Loop_Proportional_Gain : INT; {required}
   Velocity_Loop_Integral_Gain : INT; {required}
   Velocity_Feedback_Low_Pass_Filter : INT; {required}
   Position_Loop_Proportional_Gain : INT; {required}
   Position_Loop_Integral_Gain : INT; {required}
   Position_Loop_Derivative_Gain : INT; {required}
   Maximim_Position_Error_Limit : INT; {required}
END_VAR
VAR_IN_OUT
   AMCI_SV160E2_output_data : _000A:SV160E2_9125ACD4:O:0; {required}
END_VAR
VAR_OUTPUT
   EN : BOOL; {access Read Only, visible}   // AOI EN bit
   DN : BOOL; {access Read Only, visible}   // AOI DN bit
   Config_ER : BOOL; {access Read Only, visible}   // AOI ER bit
   data_block_with_error : INT; {access Read Only, visible}
   data_word_with_error : INT; {access Read Only, visible}
END_VAR
VAR
   command_data_block : INT[10];
   tuning_counter : COUNTER := (PRE := 2); {access None}
END_VAR

ROUTINE EnableInFalse   (* ladder *)
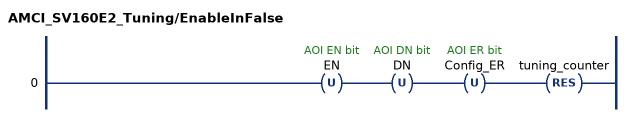
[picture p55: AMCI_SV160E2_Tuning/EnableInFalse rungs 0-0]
   0: OTU(EN)OTU(DN)OTU(Config_ER)RES(tuning_counter);
END_ROUTINE

ROUTINE Logic   (* ladder *)
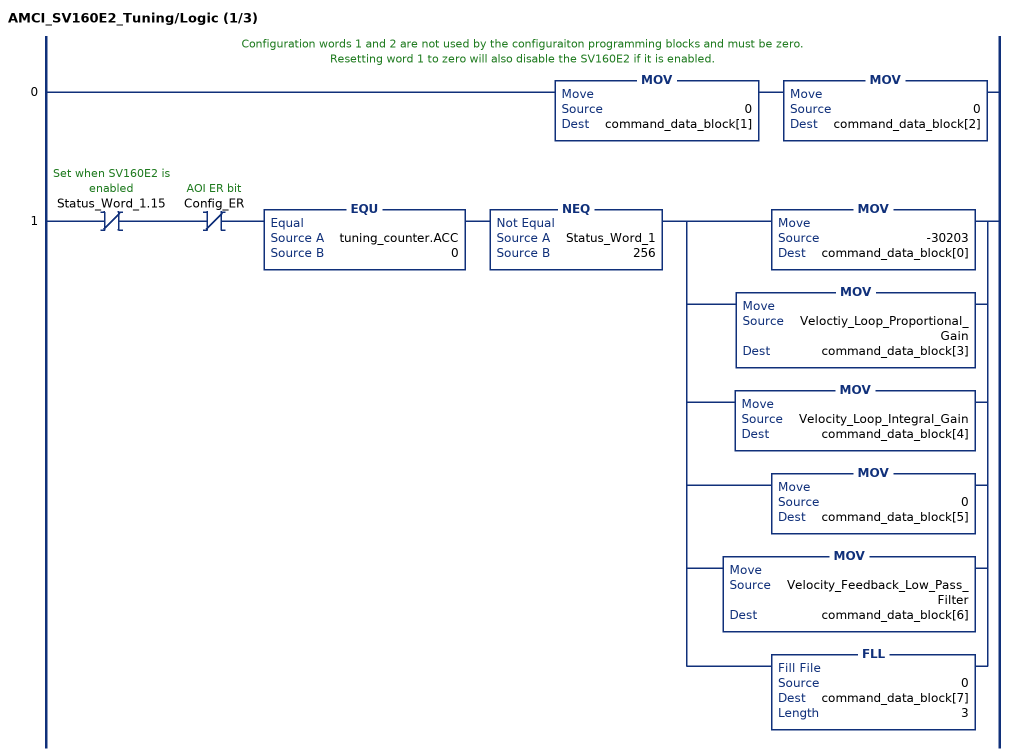
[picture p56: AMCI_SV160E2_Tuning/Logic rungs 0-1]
   // Configuration words 1 and 2 are not used by the configuraiton programming blocks and must be zero.
   // Resetting word 1 to zero will also disable the SV160E2 if it is enabled.
   0: MOV(0,command_data_block[1])MOV(0,command_data_block[2]);
   1: XIO(Status_Word_1.15)XIO(Config_ER)EQU(tuning_counter.ACC,0)NEQ(Status_Word_1,256)[MOV(-30203,command_data_block[0]) ,MOV(Veloctiy_Loop_Proportional_Gain,command_data_block[3]) ,MOV(Velocity_Loop_Integral_Gain,command_data_block[4]) ,MOV(0,command_data_block[5]) ,MOV(Velocity_Feedback_Low_Pass_Filter,command_data_block[6]) ,FLL(0,command_data_block[7],3) ];
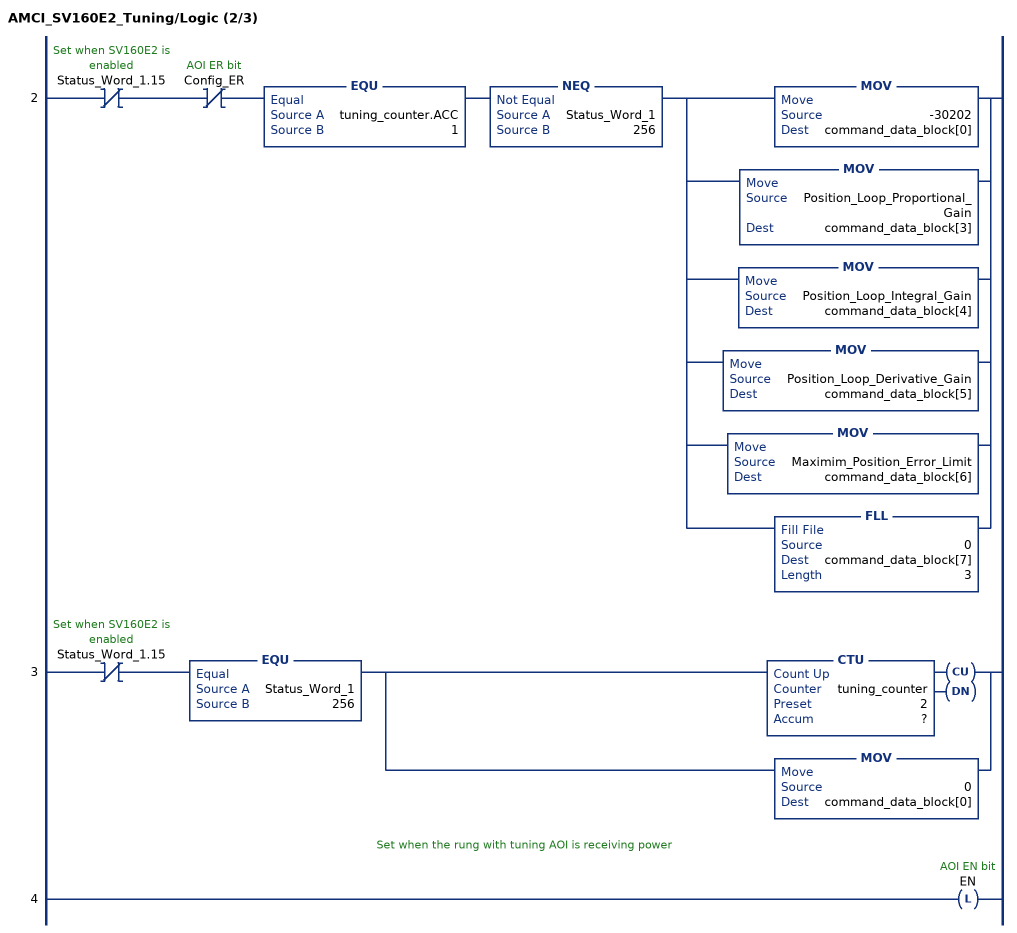
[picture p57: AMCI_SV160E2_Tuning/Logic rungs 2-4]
   2: XIO(Status_Word_1.15)XIO(Config_ER)EQU(tuning_counter.ACC,1)NEQ(Status_Word_1,256)[MOV(-30202,command_data_block[0]) ,MOV(Position_Loop_Proportional_Gain,command_data_block[3]) ,MOV(Position_Loop_Integral_Gain,command_data_block[4]) ,MOV(Position_Loop_Derivative_Gain,command_data_block[5]) ,MOV(Maximim_Position_Error_Limit,command_data_block[6]) ,FLL(0,command_data_block[7],3) ];
   3: XIO(Status_Word_1.15)EQU(Status_Word_1,256)[CTU(tuning_counter,?,?) ,MOV(0,command_data_block[0]) ];
   // Set when the rung with tuning AOI is receiving power
   4: OTL(EN);
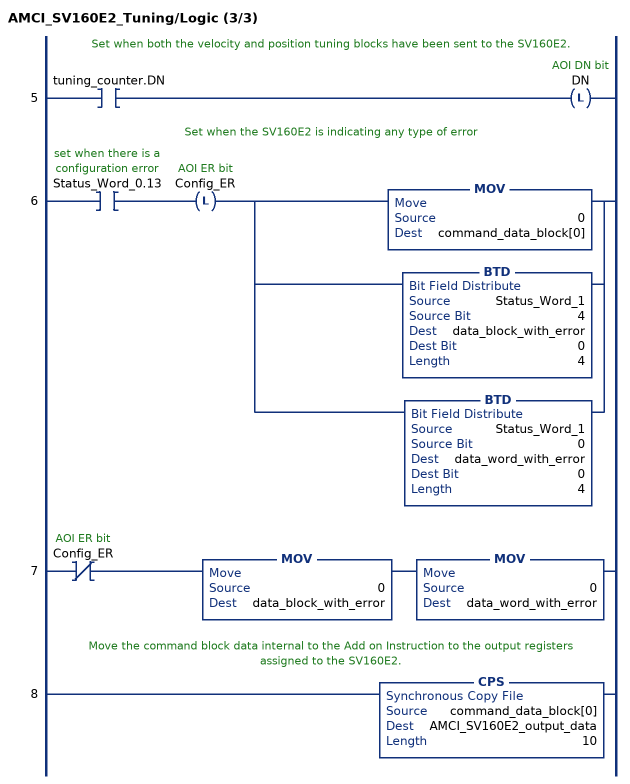
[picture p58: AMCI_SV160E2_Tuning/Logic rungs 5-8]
   // Set when both the velocity and position tuning blocks have been sent to the SV160E2.
   5: XIC(tuning_counter.DN)OTL(DN);
   // Set when the SV160E2 is indicating any type of error
   6: XIC(Status_Word_0.13)OTL(Config_ER)[MOV(0,command_data_block[0]) ,BTD(Status_Word_1,4,data_block_with_error,0,4) ,BTD(Status_Word_1,0,data_word_with_error,0,4) ];
   7: XIO(Config_ER)MOV(0,data_block_with_error)MOV(0,data_word_with_error);
   // Move the command block data internal to the Add on Instruction to the output registers assigned to the SV160E2.
   8: CPS(command_data_block[0],AMCI_SV160E2_output_data,10);
END_ROUTINE
END_ADD_ON_INSTRUCTION

VAR_GLOBAL   (* controller tags *)
   AMCI_Sample_Master : AXIS_VIRTUAL;
   AMCI_sample_motion_group : MOTION_GROUP;
   buffered_SV160E2_data : INT[10] := ([1] := -16384, [9] := -28672);
        [0].0   // set when the SV160E2 is moving CW
        [0].1   // set when SV160E2 is moving CCW
        [0].3   // set when SV160E2 is stopped
        [0].4   // set when SV160E2 is accelerating
        [0].6   // set when SV160E2 is decelerating
        [0].5   // set when SV160E2 is accelerating
   comment_coil : DINT;
   conversion_constant_read : REAL;
   jog_CW_programmed_speed : DINT := 20000;
   maximum_move_torque : INT;
   position_unwind_read : DINT;
   preset_target_position : DINT;
   relative_move_programmed_speed : DINT := 16384;
   run_SV160E2 : DINT;   // 1=relative move 2=jog CW 3=jog CCW 4=reset errors 5=home CW 6=preset position 7=tuning 8=circular follower 9=linear follower
   SV160E2_acceleration : DINT;
   SV160E2_communication_status : DINT;
   SV160E2_Position_difference : DINT;
   SV160E2_programmed_speed : DINT;
   SV160E2_target_position : DINT;
END_VAR

PROGRAM MainProgram   (* main routine MainRoutine *)
VAR
   motion_axis_1 : MOTION_INSTRUCTION;
   motion_axis_2 : MOTION_INSTRUCTION;
   SV160E2_Absolute_Move_AOI : AMCI_SV160E2_Absolute_Move;
   SV160E2_axis_follower_circular : AMCI_SV160E2_Axis_Follower_Circular;
   SV160E2_Disable_AOI : AMCI_SV160E2_Disable;
   SV160E2_Enable_AOI : AMCI_SV160E2_Enable;
   SV160E2_Hold_AOI : AMCI_SV160E2_Hold;
   SV160E2_Home_CCW_AOI : AMCI_SV160E2_Home_CCW;
   SV160E2_Home_CW_AOI : AMCI_SV160E2_Home_CW;
   SV160E2_Immediate_stop_AOI : AMCI_SV160E2_Immediate_Stop;
   SV160E2_Jog_CCW_AOI : AMCI_SV160E2_Jog_CCW;
   SV160E2_Jog_CW_AOI : AMCI_SV160E2_Jog_CW;
   SV160E2_linear_follower_AOI : AMCI_SV160E2_Axis_Follower_Linear;
   SV160E2_preset_on_enable_AOI : AMCI_SV160E2_Preset_on_Enable;
   SV160E2_Preset_Position_AOI : AMCI_SV160E2_Preset_Position;
   SV160E2_Registration_CCW_AOI : AMCI_SV160E2_Registration_Move_CCW;
   SV160E2_Registration_CW_AOI : AMCI_SV160E2_Registration_Move_CW;
   SV160E2_relative_move_AOI : AMCI_SV160E2_Relative_Move;
   SV160E2_reset_errors_AOI : AMCI_SV160E2_Reset_Errors;
   SV160E2_Resume_AOI : AMCI_SV160E2_Resume;
   SV160E2_Tuning_AOI : AMCI_SV160E2_Tuning;
END_VAR

ROUTINE axis_follower_circular   (* ladder *)
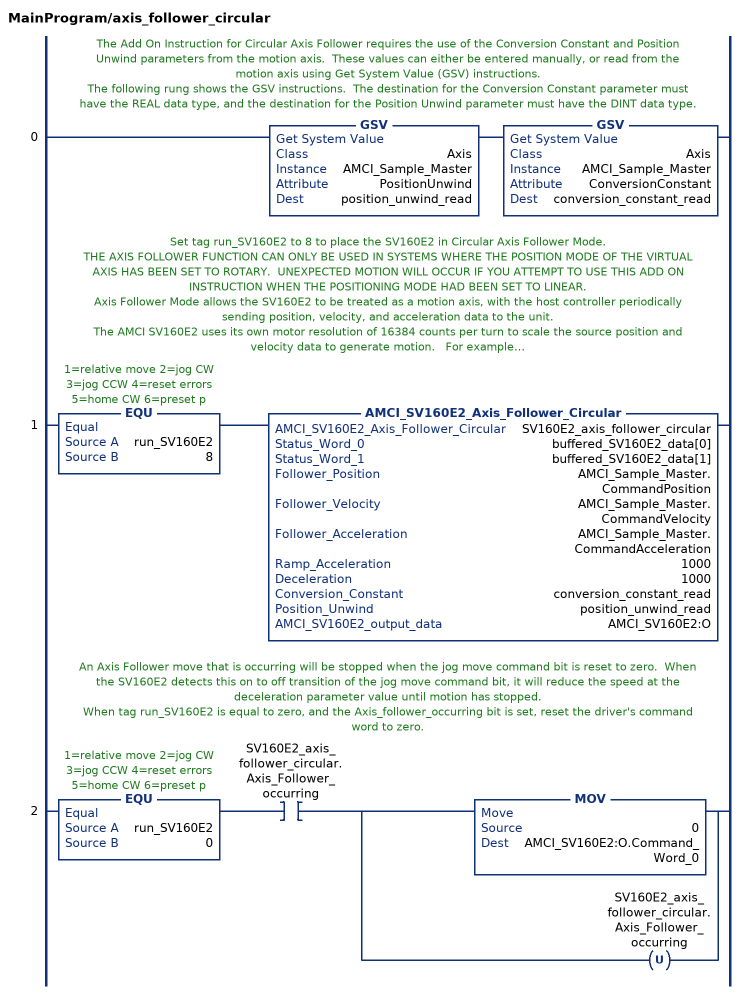
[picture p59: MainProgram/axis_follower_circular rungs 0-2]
   // The Add On Instruction for Circular Axis Follower requires the use of the Conversion Constant and Position Unwind parameters from the motion axis.  These values can either be entered manually, or read from the motion axis using Get System Value (GSV) instructions.
   // The following rung shows the GSV instructions.  The destination for the Conversion Constant parameter must have the REAL data type, and the destination for the Position Unwind parameter must have the DINT data type.
   0: GSV(Axis,AMCI_Sample_Master,PositionUnwind,position_unwind_read)GSV(Axis,AMCI_Sample_Master,ConversionConstant,conversion_constant_read);
   // Set tag run_SV160E2 to 8 to place the SV160E2 in Circular Axis Follower Mode.
   // THE AXIS FOLLOWER FUNCTION CAN ONLY BE USED IN SYSTEMS WHERE THE POSITION MODE OF THE VIRTUAL AXIS HAS BEEN SET TO ROTARY.  UNEXPECTED MOTION WILL OCCUR IF YOU ATTEMPT TO USE THIS ADD ON INSTRUCTION WHEN THE POSITIONING MODE HAD BEEN SET TO LINEAR.
   // Axis Follower Mode allows the SV160E2 to be treated as a motion axis, with the host controller periodically sending position, velocity, and acceleration data to the unit.
   // The AMCI SV160E2 uses its own motor resolution of 16384 counts per turn to scale the source position and velocity data to generate motion.   For example,
   // Unwind Value = 65536
   // Conversion Constant = 16384
   // Commanded Motion Axis speed is set to 2 rev / sec
   // Motor Steps / Turn = 16384
   // The position data from the motion axis will have a range of 0 to 4.  This is the unwind value divided by the conversion constant.
   // The velocity data from the motion axis will have a range of 0 to 2.
   // After multiplying by the conversion constant, the position sent to the AMCI Motion Controller will have a range of 0 to 65536 steps and the velocity will have a value of 32768 steps / sec.
   // The motor will turn at ((32768 steps / sec) / (16384 steps / rev)) or at 2 rev / sec
   // Note: The SV160E2 will generate a command error if the result of multiplying the motion axis velocity by the conversion constant exceeds 1,048,575 steps / sec.
   // The SV160E2 will more closely follow the position and velocity generated by the motion axis if a smaller RPI time is used.  The SV160E2’s minimum RPI time is 1ms and a value of 2ms is recommended.
   // Status_Word_0:  This is the first input word, also named Status Word 0, from the SV160E2 and contains status bits that will be used by the Add On Instruction to determine when to send commands to the SV160E2 and also when to set the Motion Occurring and ER bits.
   // Status_Word_1: This is the second input word, also named Status Word 1, from the SV160E2 and contains status bits that will be used by the Add On Instruction to determine when to send commands to the SV160E2.
   // Follower_Position = REAL DATA TYPE position directly from the motion axis
   // Follower_Velocity = REAL DATA TYPE velocity directly from the motion axis
   // Follower_Acceleration = REAL DATA TYPE acceleration directly from the motion axis.  A value of 0 can also be used.
   // Ramp Acceleration = An actual value or INT value used by the SV160E2 to transition from no motion to motion.   The range is 0 to 15,999.  The larger the value the faster the SV160E2 will accelerate.  There will be no acceleration if the value is set to zero.
   // Deceleration: An actual value or an INT DATA TYPE register used by the SV160E2 to transition from motion to no motion.   The range is 1 to 15,999.  The larger the value the faster the SV160E2 will decelerate.
   // Conversion Constant = an actual value or a REAL data type register.   The value in this field is multiplied by the Position, Velocity, and Acceleration from the master axis before being sent to the SV160E2 and scales the supplied position data to the SV160E2’s motor counts per turn.   This field is typically, but does not have to be, set to the master axis’ Conversion Constant.
   // Position Unwind = an actual value or a DINT TYPE register. This parameter defines the point at which the position data will transition from its maximum to its minimum value.  This field MUST BE SET to the Position Unwind parameter that was entered on the Conversion tab of the motion axis.   The Position Unwind Value MUST BE IN THE RANGE OF 1024 TO 1,073,741,824.
   // BOOL Bit Axis_follower_occurring is a flag to indicate that an axis follower move is occurring.
   // Register run_SV160E2 is only an internal tag used to illustrate how the rung must go from false to true to make the move operation occur, and is set by either manually typing the number into the register or having your ladder logic move a value into the register.  IT IS NOT NECESSASRY TO USE THIS REGISTER OR AN EQUAL INSTRUCTION TO SEND COMMANDS TO THE AMCI SV160E2.  You can replace it with any other condition that makes the rung true, such as a push button on a HMI terminal.
   1: EQU(run_SV160E2,8)AMCI_SV160E2_Axis_Follower_Circular(SV160E2_axis_follower_circular,buffered_SV160E2_data[0],buffered_SV160E2_data[1],AMCI_Sample_Master.CommandPosition,AMCI_Sample_Master.CommandVelocity,AMCI_Sample_Master.CommandAcceleration,1000,1000,conversion_constant_read,position_unwind_read,AMCI_SV160E2:O);
   // An Axis Follower move that is occurring will be stopped when the jog move command bit is reset to zero.  When the SV160E2 detects this on to off transition of the jog move command bit, it will reduce the speed at the deceleration parameter value until motion has stopped.
   // When tag run_SV160E2 is equal to zero, and the Axis_follower_occurring bit is set, reset the driver's command word to zero.
   2: EQU(run_SV160E2,0)XIC(SV160E2_axis_follower_circular.Axis_Follower_occurring)[MOV(0,AMCI_SV160E2:O.Command_Word_0) ,OTU(SV160E2_axis_follower_circular.Axis_Follower_occurring) ];
END_ROUTINE

ROUTINE Axis_follower_linear   (* ladder *)
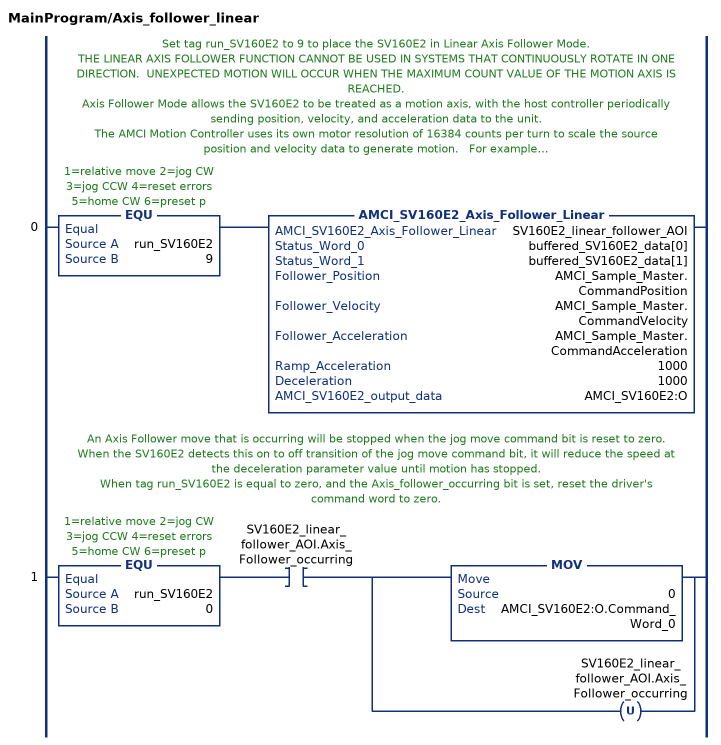
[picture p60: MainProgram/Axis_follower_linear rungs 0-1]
   // Set tag run_SV160E2 to 9 to place the SV160E2 in Linear Axis Follower Mode.
   // THE LINEAR AXIS FOLLOWER FUNCTION CANNOT BE USED IN SYSTEMS THAT CONTINUOUSLY ROTATE IN ONE DIRECTION.  UNEXPECTED MOTION WILL OCCUR WHEN THE MAXIMUM COUNT VALUE OF THE MOTION AXIS IS REACHED.
   // Axis Follower Mode allows the SV160E2 to be treated as a motion axis, with the host controller periodically sending position, velocity, and acceleration data to the unit.
   // The AMCI Motion Controller uses its own motor resolution of 16384 counts per turn to scale the source position and velocity data to generate motion.   For example,
   // The Motion Axis is sending 20000 steps / sec to the SV160E2
   // The SV160E2 is configured for 16384 steps / rev
   // The motor will turn at ((20000 steps / sec) / (16384 steps / rev)) or at 1.22 rev / sec
   // The SV160E2 will more closely follow the position and velocity generated by the motion axis if a smaller RPI time is used.  The SV160E2’s minimum RPI time is 1ms and a value of 2ms is recommended.
   // Status_Word_0:  This is the first input word, also named Status Word 0, from the SV160E2 and contains status bits that will be used by the Add On Instruction to determine when to send commands to the SV160E2 and also when to set the Motion Occurring and ER bits.
   // Status_Word_1: This is the second input word, also named Status Word 1, from the SV160E2 and contains status bits that will be used by the Add On Instruction to determine when to send commands to the SV160E2.
   // Follower_Position = REAL DATA TYPE position directly from the motion axis
   // Follower_Velocity = REAL DATA TYPE velocity directly from the motion axis
   // Follower_Acceleration = REAL DATA TYPE acceleration directly from the motion axis.  A value of 0 can also be used.
   // Ramp Acceleration = An actual value or INT value used by the SV160E2 to transition from no motion to motion.   The range is 0 to 15,999.  The larger the value the faster the SV160E2 will accelerate.  There will be no acceleration if the value is set to zero.
   // Deceleration: An actual value or an INT DATA TYPE register used by the SV160E2 to transition from motion to no motion.   The range is 1 to 15,999.  The larger the value the faster the SV160E2 will decelerate.
   // BOOL Bit Axis_follower_occurring is a flag to indicate that an axis follower move is occurring.
   // Register run_SV160E2 is only an internal tag used to illustrate how the rung must go from false to true to make the move operation occur, and is set by either manually typing the number into the register or having your ladder logic move a value into the register.  IT IS NOT NECESSASRY TO USE THIS REGISTER OR AN EQUAL INSTRUCTION TO SEND COMMANDS TO THE AMCI SV160E2.  You can replace it with any other condition that makes the rung true, such as a push button on a HMI terminal.
   0: EQU(run_SV160E2,9)AMCI_SV160E2_Axis_Follower_Linear(SV160E2_linear_follower_AOI,buffered_SV160E2_data[0],buffered_SV160E2_data[1],AMCI_Sample_Master.CommandPosition,AMCI_Sample_Master.CommandVelocity,AMCI_Sample_Master.CommandAcceleration,1000,1000,AMCI_SV160E2:O);
   // An Axis Follower move that is occurring will be stopped when the jog move command bit is reset to zero.  When the SV160E2 detects this on to off transition of the jog move command bit, it will reduce the speed at the deceleration parameter value until motion has stopped.
   // When tag run_SV160E2 is equal to zero, and the Axis_follower_occurring bit is set, reset the driver's command word to zero.
   1: EQU(run_SV160E2,0)XIC(SV160E2_linear_follower_AOI.Axis_Follower_occurring)[MOV(0,AMCI_SV160E2:O.Command_Word_0) ,OTU(SV160E2_linear_follower_AOI.Axis_Follower_occurring) ];
END_ROUTINE

ROUTINE MainRoutine   (* ladder *)
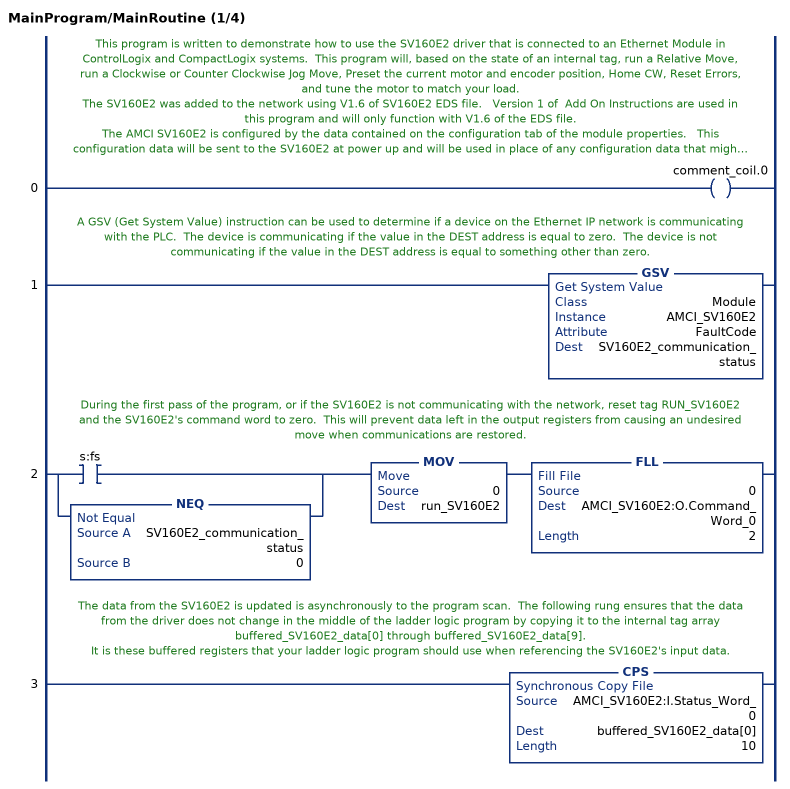
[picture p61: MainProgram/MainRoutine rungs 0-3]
   // This program is written to demonstrate how to use the SV160E2 driver that is connected to an Ethernet Module in ControlLogix and CompactLogix systems.  This program will, based on the state of an internal tag, run a Relative Move, run a Clockwise or Counter Clockwise Jog Move, Preset the current motor and encoder position, Home CW, Reset Errors, and tune the motor to match your load.
   // The SV160E2 was added to the network using V1.6 of SV160E2 EDS file.   Version 1 of  Add On Instructions are used in this program and will only function with V1.6 of the EDS file.
   // The AMCI SV160E2 is configured by the data contained on the configuration tab of the module properties.   This configuration data will be sent to the SV160E2 at power up and will be used in place of any configuration data that might be stored in the SV160E2’s flash memory.
   // The configuration data in the EDS tile contains default tuning parameters that assume the SV160E2 is unloaded.  You will most likely have to adjust these tuning parameters to more closely match your system.  Please see the user manual for tables of suggested tuning values based on the load.
   // There is no requirement for you to use internal tag run_SV160E2.  It is only intended for use in this sample program and can be replaced by any condition, such as a push button on your HMI, that works best in your application.
   // CPS instructions are used in place of COP instructions to ensure that the transfer of data from the PLC to the SV160E2 is not interrupted by RPI I/O update of the driver.
   // This program uses Add On Instructions for most of the SV160E2's functions.  These instructions prompt you for what data is required for the requested move operation, set / reset the appropriate control bits and words, and enable the driver.  Although they are all not shown in the program, Add On Instructions for most of the SV160E2's functions are available in the Add-On Instructions section of the project tree.
   // Some of the Add On Instructions have some of the less commonly used functions, such as Indexed Moves or Maximum Move Torque, hidden.   The Add On Instructions are not locked or protected and, if desired, these functions can be made visible and enabled.
   // This sample program has subroutines that explain and show the use of the linear and circular axis follower functions.  Ignore or delete these subroutines if you are not using these functions.
   0: OTE(comment_coil.0);
   // A GSV (Get System Value) instruction can be used to determine if a device on the Ethernet IP network is communicating with the PLC.  The device is communicating if the value in the DEST address is equal to zero.  The device is not communicating if the value in the DEST address is equal to something other than zero.
   1: GSV(Module,AMCI_SV160E2,FaultCode,SV160E2_communication_status);
   // During the first pass of the program, or if the SV160E2 is not communicating with the network, reset tag RUN_SV160E2 and the SV160E2's command word to zero.  This will prevent data left in the output registers from causing an undesired move when communications are restored.
   2: [XIC(s:fs) ,NEQ(SV160E2_communication_status,0) ]MOV(0,run_SV160E2)FLL(0,AMCI_SV160E2:O.Command_Word_0,2);
   // The data from the SV160E2 is updated is asynchronously to the program scan.  The following rung ensures that the data from the driver does not change in the middle of the ladder logic program by copying it to the internal tag array buffered_SV160E2_data[0] through buffered_SV160E2_data[9].
   // It is these buffered registers that your ladder logic program should use when referencing the SV160E2's input data.
   3: CPS(AMCI_SV160E2:I.Status_Word_0,buffered_SV160E2_data[0],10);
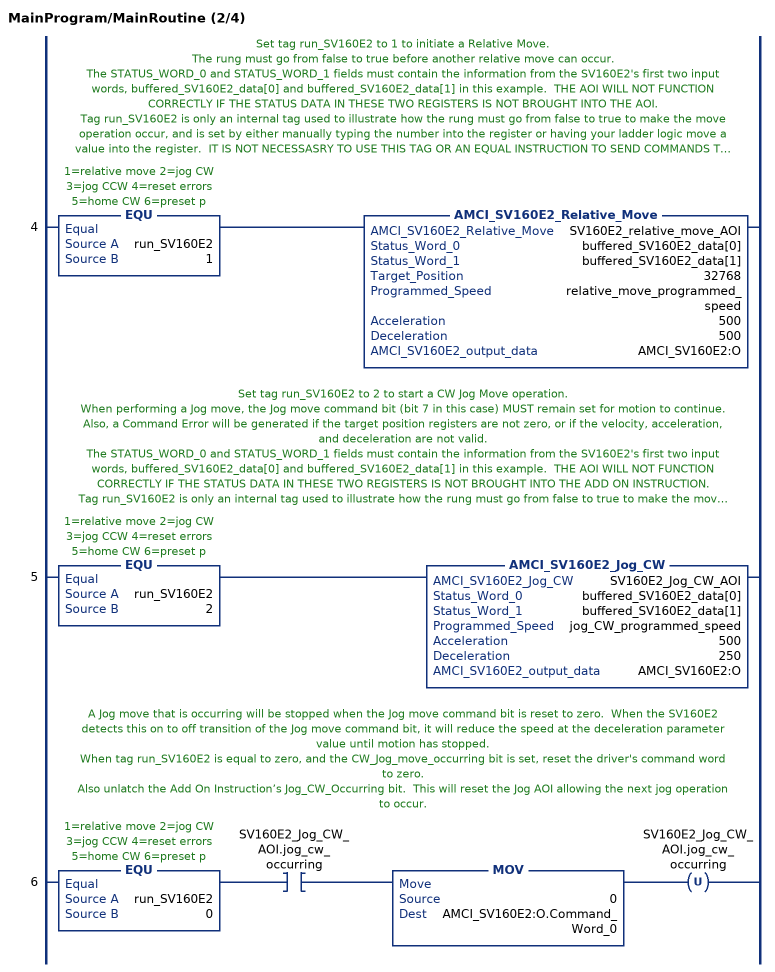
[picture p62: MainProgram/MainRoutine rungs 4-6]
   // Set tag run_SV160E2 to 1 to initiate a Relative Move.
   // The rung must go from false to true before another relative move can occur.
   // The STATUS_WORD_0 and STATUS_WORD_1 fields must contain the information from the SV160E2's first two input words, buffered_SV160E2_data[0] and buffered_SV160E2_data[1] in this example.  THE AOI WILL NOT FUNCTION CORRECTLY IF THE STATUS DATA IN THESE TWO REGISTERS IS NOT BROUGHT INTO THE AOI.
   // Tag run_SV160E2 is only an internal tag used to illustrate how the rung must go from false to true to make the move operation occur, and is set by either manually typing the number into the register or having your ladder logic move a value into the register.  IT IS NOT NECESSASRY TO USE THIS TAG OR AN EQUAL INSTRUCTION TO SEND COMMANDS TO THE AMCI SV160E2.  You can replace it with any other condition that makes the rung true, such as a push button on a HMI terminal
   4: EQU(run_SV160E2,1)AMCI_SV160E2_Relative_Move(SV160E2_relative_move_AOI,buffered_SV160E2_data[0],buffered_SV160E2_data[1],32768,relative_move_programmed_speed,500,500,AMCI_SV160E2:O);
   // Set tag run_SV160E2 to 2 to start a CW Jog Move operation.
   // When performing a Jog move, the Jog move command bit (bit 7 in this case) MUST remain set for motion to continue.  Also, a Command Error will be generated if the target position registers are not zero, or if the velocity, acceleration, and deceleration are not valid.
   // The STATUS_WORD_0 and STATUS_WORD_1 fields must contain the information from the SV160E2's first two input words, buffered_SV160E2_data[0] and buffered_SV160E2_data[1] in this example.  THE AOI WILL NOT FUNCTION CORRECTLY IF THE STATUS DATA IN THESE TWO REGISTERS IS NOT BROUGHT INTO THE ADD ON INSTRUCTION.
   // Tag run_SV160E2 is only an internal tag used to illustrate how the rung must go from false to true to make the move operation occur, and is set by either manually typing the number into the register or having your ladder logic move a value into the register.  IT IS NOT NECESSASRY TO USE THIS TAG OR AN EQUAL INSTRUCTION TO SEND COMMANDS TO THE AMCI SV160E2.  You can replace it with any other condition that makes the rung true, such as a push button on a HMI terminal.
   5: EQU(run_SV160E2,2)AMCI_SV160E2_Jog_CW(SV160E2_Jog_CW_AOI,buffered_SV160E2_data[0],buffered_SV160E2_data[1],jog_CW_programmed_speed,500,250,AMCI_SV160E2:O);
   // A Jog move that is occurring will be stopped when the Jog move command bit is reset to zero.  When the SV160E2 detects this on to off transition of the Jog move command bit, it will reduce the speed at the deceleration parameter value until motion has stopped.
   // When tag run_SV160E2 is equal to zero, and the CW_Jog_move_occurring bit is set, reset the driver's command word to zero.
   // Also unlatch the Add On Instruction’s Jog_CW_Occurring bit.  This will reset the Jog AOI allowing the next jog operation to occur.
   6: EQU(run_SV160E2,0)XIC(SV160E2_Jog_CW_AOI.jog_cw_occurring)MOV(0,AMCI_SV160E2:O.Command_Word_0)OTU(SV160E2_Jog_CW_AOI.jog_cw_occurring);
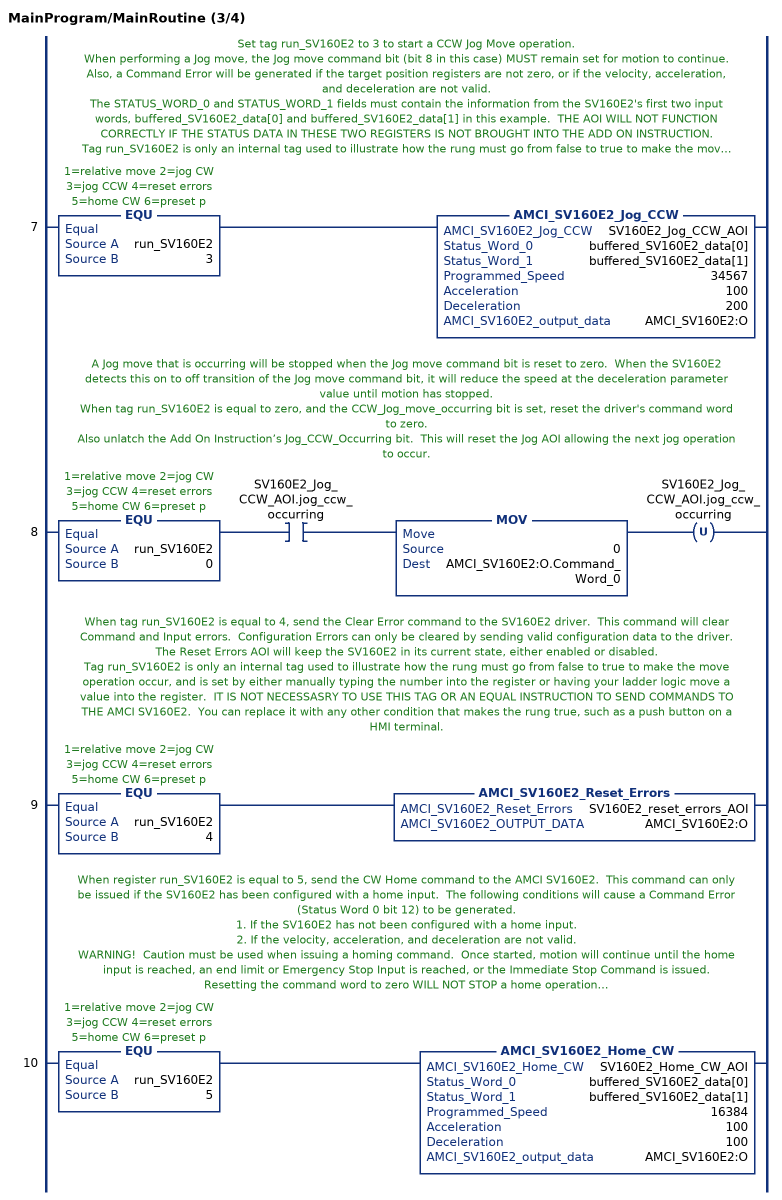
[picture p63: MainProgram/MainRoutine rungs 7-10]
   // Set tag run_SV160E2 to 3 to start a CCW Jog Move operation.
   // When performing a Jog move, the Jog move command bit (bit 8 in this case) MUST remain set for motion to continue.  Also, a Command Error will be generated if the target position registers are not zero, or if the velocity, acceleration, and deceleration are not valid.
   // The STATUS_WORD_0 and STATUS_WORD_1 fields must contain the information from the SV160E2's first two input words, buffered_SV160E2_data[0] and buffered_SV160E2_data[1] in this example.  THE AOI WILL NOT FUNCTION CORRECTLY IF THE STATUS DATA IN THESE TWO REGISTERS IS NOT BROUGHT INTO THE ADD ON INSTRUCTION.
   // Tag run_SV160E2 is only an internal tag used to illustrate how the rung must go from false to true to make the move operation occur, and is set by either manually typing the number into the register or having your ladder logic move a value into the register.  IT IS NOT NECESSASRY TO USE THIS TAG OR AN EQUAL INSTRUCTION TO SEND COMMANDS TO THE AMCI SV160E2.  You can replace it with any other condition that makes the rung true, such as a push button on a HMI terminal.
   7: EQU(run_SV160E2,3)AMCI_SV160E2_Jog_CCW(SV160E2_Jog_CCW_AOI,buffered_SV160E2_data[0],buffered_SV160E2_data[1],34567,100,200,AMCI_SV160E2:O);
   // A Jog move that is occurring will be stopped when the Jog move command bit is reset to zero.  When the SV160E2 detects this on to off transition of the Jog move command bit, it will reduce the speed at the deceleration parameter value until motion has stopped.
   // When tag run_SV160E2 is equal to zero, and the CCW_Jog_move_occurring bit is set, reset the driver's command word to zero.
   // Also unlatch the Add On Instruction’s Jog_CCW_Occurring bit.  This will reset the Jog AOI allowing the next jog operation to occur.
   8: EQU(run_SV160E2,0)XIC(SV160E2_Jog_CCW_AOI.jog_ccw_occurring)MOV(0,AMCI_SV160E2:O.Command_Word_0)OTU(SV160E2_Jog_CCW_AOI.jog_ccw_occurring);
   // When tag run_SV160E2 is equal to 4, send the Clear Error command to the SV160E2 driver.  This command will clear Command and Input errors.  Configuration Errors can only be cleared by sending valid configuration data to the driver.
   // The Reset Errors AOI will keep the SV160E2 in its current state, either enabled or disabled.
   // Tag run_SV160E2 is only an internal tag used to illustrate how the rung must go from false to true to make the move operation occur, and is set by either manually typing the number into the register or having your ladder logic move a value into the register.  IT IS NOT NECESSASRY TO USE THIS TAG OR AN EQUAL INSTRUCTION TO SEND COMMANDS TO THE AMCI SV160E2.  You can replace it with any other condition that makes the rung true, such as a push button on a HMI terminal.
   9: EQU(run_SV160E2,4)AMCI_SV160E2_Reset_Errors(SV160E2_reset_errors_AOI,AMCI_SV160E2:O);
   // When register run_SV160E2 is equal to 5, send the CW Home command to the AMCI SV160E2.  This command can only be issued if the SV160E2 has been configured with a home input.  The following conditions will cause a Command Error (Status Word 0 bit 12) to be generated.
   // 1. If the SV160E2 has not been configured with a home input.
   // 2. If the velocity, acceleration, and deceleration are not valid.
   // WARNING!  Caution must be used when issuing a homing command.  Once started, motion will continue until the home input is reached, an end limit or Emergency Stop Input is reached, or the Immediate Stop Command is issued.  Resetting the command word to zero WILL NOT STOP a home operation.
   // The STATUS_WORD_0 and STATUS_WORD_1 fields must contain the information from the SV160E2's first two input words, buffered_SV160E2_data[0] and buffered_SV160E2_data[1] in this example.  THE AOI WILL NOT FUNCTION CORRECTLY IF THE STATUS DATA IN THESE TWO REGISTERS IS NOT BROUGHT INTO THE ADD ON INSTRUCTION.
   // Register run_SV160E2 is only an internal tag used to illustrate how the rung must go from false to true to make the move operation occur, and is set by either manually typing the number into the register or having your ladder logic move a value into the register.  IT IS NOT NECESSASRY TO USE THIS REGISTER OR AN EQUAL INSTRUCTION TO SEND COMMANDS TO THE AMCI SV160E2.  You can replace it with any other condition that makes the rung true, such as a push button on a HMI terminal.
   10: EQU(run_SV160E2,5)AMCI_SV160E2_Home_CW(SV160E2_Home_CW_AOI,buffered_SV160E2_data[0],buffered_SV160E2_data[1],16384,100,100,AMCI_SV160E2:O);
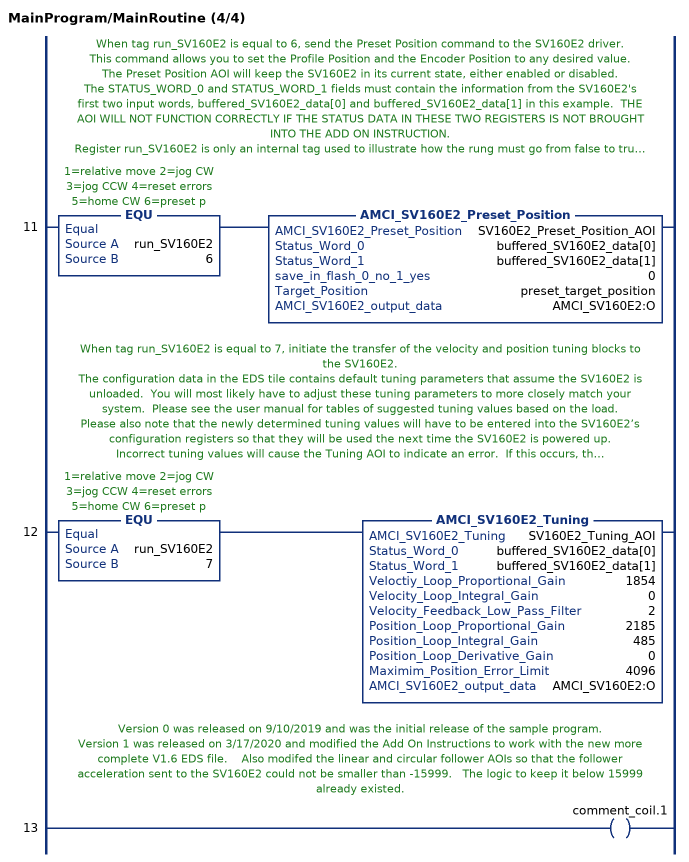
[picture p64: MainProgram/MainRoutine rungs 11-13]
   // When tag run_SV160E2 is equal to 6, send the Preset Position command to the SV160E2 driver.
   // This command allows you to set the Profile Position and the Encoder Position to any desired value.
   // The Preset Position AOI will keep the SV160E2 in its current state, either enabled or disabled.
   // The STATUS_WORD_0 and STATUS_WORD_1 fields must contain the information from the SV160E2's first two input words, buffered_SV160E2_data[0] and buffered_SV160E2_data[1] in this example.  THE AOI WILL NOT FUNCTION CORRECTLY IF THE STATUS DATA IN THESE TWO REGISTERS IS NOT BROUGHT INTO THE ADD ON INSTRUCTION.
   // Register run_SV160E2 is only an internal tag used to illustrate how the rung must go from false to true to make the move operation occur, and is set by either manually typing the number into the register or having your ladder logic move a value into the register.  IT IS NOT NECESSASRY TO USE THIS REGISTER OR AN EQUAL INSTRUCTION TO SEND COMMANDS TO THE AMCI SV160E2.  You can replace it with any other condition that makes the rung true, such as a push button on a HMI terminal.
   11: EQU(run_SV160E2,6)AMCI_SV160E2_Preset_Position(SV160E2_Preset_Position_AOI,buffered_SV160E2_data[0],buffered_SV160E2_data[1],0,preset_target_position,AMCI_SV160E2:O);
   // When tag run_SV160E2 is equal to 7, initiate the transfer of the velocity and position tuning blocks to the SV160E2.
   // The configuration data in the EDS tile contains default tuning parameters that assume the SV160E2 is unloaded.  You will most likely have to adjust these tuning parameters to more closely match your system.  Please see the user manual for tables of suggested tuning values based on the load.
   // Please also note that the newly determined tuning values will have to be entered into the SV160E2’s configuration registers so that they will be used the next time the SV160E2 is powered up.
   // Incorrect tuning values will cause the Tuning AOI to indicate an error.  If this occurs, the Data_Block_with_Error field will indicate which data block, “5” for velocity tuning or “6” for position tuning, has the error.  The Data_Word_with_Error field will indicate which word in the data block has the error.  Please see the SV160E2 manual for more information.
   // The STATUS_WORD_0 and STATUS_WORD_1 fields must contain the information from the SV160E2's first two input words, buffered_SV160E2_data[0] and buffered_SV160E2_data[1] in this example.  THE AOI WILL NOT FUNCTION CORRECTLY IF THE STATUS DATA IN THESE TWO REGISTERS IS NOT BROUGHT INTO THE ADD ON INSTRUCTION.
   // Register run_SV160E2 is only an internal tag used to illustrate how the rung must go from false to true to make the move operation occur, and is set by either manually typing the number into the register or having your ladder logic move a value into the register.  IT IS NOT NECESSASRY TO USE THIS REGISTER OR AN EQUAL INSTRUCTION TO SEND COMMANDS TO THE AMCI SV160E2.  You can replace it with any other condition that makes the rung true, such as a push button on a HMI terminal.
   12: EQU(run_SV160E2,7)AMCI_SV160E2_Tuning(SV160E2_Tuning_AOI,buffered_SV160E2_data[0],buffered_SV160E2_data[1],1854,0,2,2185,485,0,4096,AMCI_SV160E2:O);
   // Version 0 was released on 9/10/2019 and was the initial release of the sample program.
   // Version 1 was released on 3/17/2020 and modified the Add On Instructions to work with the new more complete V1.6 EDS file.    Also modifed the linear and circular follower AOIs so that the follower acceleration sent to the SV160E2 could not be smaller than -15999.   The logic to keep it below 15999 already existed.
   13: OTE(comment_coil.1);
END_ROUTINE
END_PROGRAM
